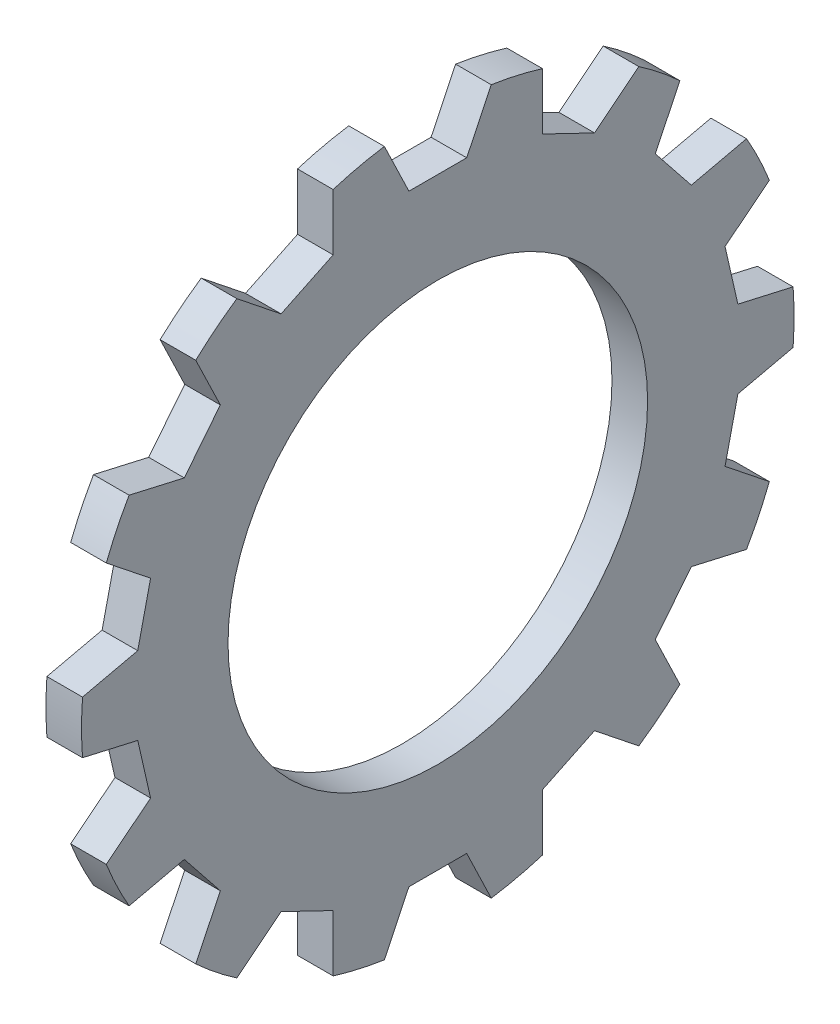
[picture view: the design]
ISO-10303-21;
HEADER;
FILE_DESCRIPTION(('STEP AP214'),'2;1');
FILE_NAME('part.step','',(''),(''),'','','');
FILE_SCHEMA(('AUTOMOTIVE_DESIGN { 1 0 10303 214 1 1 1 1 }'));
ENDSEC;
DATA;
#1=APPLICATION_CONTEXT('core data for automotive mechanical design processes');
#2=APPLICATION_PROTOCOL_DEFINITION('international standard','automotive_design',2000,#1);
#3=PRODUCT_CONTEXT('',#1,'mechanical');
#4=PRODUCT('Part','Part','',(#3));
#5=PRODUCT_RELATED_PRODUCT_CATEGORY('part','',(#4));
#6=PRODUCT_DEFINITION_FORMATION('','',#4);
#7=PRODUCT_DEFINITION_CONTEXT('part definition',#1,'design');
#8=PRODUCT_DEFINITION('design','',#6,#7);
#9=PRODUCT_DEFINITION_SHAPE('','',#8);
#10=(LENGTH_UNIT() NAMED_UNIT(*) SI_UNIT(.MILLI.,.METRE.));
#11=(NAMED_UNIT(*) PLANE_ANGLE_UNIT() SI_UNIT($,.RADIAN.));
#12=(NAMED_UNIT(*) SI_UNIT($,.STERADIAN.) SOLID_ANGLE_UNIT());
#13=UNCERTAINTY_MEASURE_WITH_UNIT(LENGTH_MEASURE(1.E-05),#10,'distance_accuracy_value','');
#14=(GEOMETRIC_REPRESENTATION_CONTEXT(3) GLOBAL_UNCERTAINTY_ASSIGNED_CONTEXT((#13)) GLOBAL_UNIT_ASSIGNED_CONTEXT((#10,
#11,#12)) REPRESENTATION_CONTEXT('',''));
#15=CARTESIAN_POINT('',(0.,0.,0.));
#16=DIRECTION('',(0.,0.,1.));
#17=DIRECTION('',(1.,0.,0.));
#18=AXIS2_PLACEMENT_3D('',#15,#16,#17);
#19=CARTESIAN_POINT('',(-1.143,0.,0.));
#20=DIRECTION('',(1.,0.,0.));
#21=DIRECTION('',(0.,0.,-1.));
#22=AXIS2_PLACEMENT_3D('',#19,#20,#21);
#23=CYLINDRICAL_SURFACE('',#22,11.43);
#24=DIRECTION('',(1.,0.,0.));
#25=VECTOR('',#24,1.);
#26=CARTESIAN_POINT('',(-1.143,8.38630939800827,7.76625486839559));
#27=LINE('',#26,#25);
#28=CARTESIAN_POINT('',(-1.143,8.38630939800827,7.76625486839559));
#29=VERTEX_POINT('',#28);
#30=CARTESIAN_POINT('',(0.,8.38630939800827,7.76625486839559));
#31=VERTEX_POINT('',#30);
#32=EDGE_CURVE('E476',#29,#31,#27,.T.);
#33=ORIENTED_EDGE('',*,*,#32,.T.);
#34=CARTESIAN_POINT('',(0.,0.,0.));
#35=DIRECTION('',(1.,0.,0.));
#36=DIRECTION('',(0.,0.,-1.));
#37=AXIS2_PLACEMENT_3D('',#34,#35,#36);
#38=CIRCLE('',#37,11.43);
#39=CARTESIAN_POINT('',(0.,9.43766804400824,6.44789282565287));
#40=VERTEX_POINT('',#39);
#41=EDGE_CURVE('E787',#40,#31,#38,.T.);
#42=ORIENTED_EDGE('',*,*,#41,.F.);
#43=DIRECTION('',(1.,0.,0.));
#44=VECTOR('',#43,1.);
#45=CARTESIAN_POINT('',(-1.143,9.43766804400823,6.44789282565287));
#46=LINE('',#45,#44);
#47=CARTESIAN_POINT('',(-1.143,9.43766804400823,6.44789282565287));
#48=VERTEX_POINT('',#47);
#49=EDGE_CURVE('E458',#48,#40,#46,.T.);
#50=ORIENTED_EDGE('',*,*,#49,.F.);
#51=CARTESIAN_POINT('',(-1.143,0.,0.));
#52=DIRECTION('',(1.,0.,0.));
#53=DIRECTION('',(0.,0.,-1.));
#54=AXIS2_PLACEMENT_3D('',#51,#52,#53);
#55=CIRCLE('',#54,11.43);
#56=EDGE_CURVE('E42',#48,#29,#55,.T.);
#57=ORIENTED_EDGE('',*,*,#56,.T.);
#58=EDGE_LOOP('',(#33,#42,#50,#57));
#59=FACE_BOUND('',#58,.T.);
#60=ADVANCED_FACE('F33',(#59),#23,.T.);
#61=DIRECTION('',(1.,0.,0.));
#62=VECTOR('',#61,1.);
#63=CARTESIAN_POINT('',(-1.143,5.70540924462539,9.90420139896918));
#64=LINE('',#63,#62);
#65=CARTESIAN_POINT('',(-1.143,5.70540924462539,9.90420139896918));
#66=VERTEX_POINT('',#65);
#67=CARTESIAN_POINT('',(0.,5.70540924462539,9.90420139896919));
#68=VERTEX_POINT('',#67);
#69=EDGE_CURVE('E393',#66,#68,#64,.T.);
#70=ORIENTED_EDGE('',*,*,#69,.F.);
#71=CARTESIAN_POINT('',(-1.143,4.18615198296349,10.6358371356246));
#72=VERTEX_POINT('',#71);
#73=EDGE_CURVE('E408',#66,#72,#55,.T.);
#74=ORIENTED_EDGE('',*,*,#73,.T.);
#75=DIRECTION('',(1.,0.,0.));
#76=VECTOR('',#75,1.);
#77=CARTESIAN_POINT('',(-1.143,4.18615198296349,10.6358371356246));
#78=LINE('',#77,#76);
#79=CARTESIAN_POINT('',(0.,4.18615198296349,10.6358371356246));
#80=VERTEX_POINT('',#79);
#81=EDGE_CURVE('E747',#72,#80,#78,.T.);
#82=ORIENTED_EDGE('',*,*,#81,.T.);
#83=EDGE_CURVE('E410',#68,#80,#38,.T.);
#84=ORIENTED_EDGE('',*,*,#83,.F.);
#85=EDGE_LOOP('',(#70,#74,#82,#84));
#86=FACE_BOUND('',#85,.T.);
#87=ADVANCED_FACE('F406',(#86),#23,.T.);
#88=DIRECTION('',(1.,0.,0.));
#89=VECTOR('',#88,1.);
#90=CARTESIAN_POINT('',(-1.143,0.843124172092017,11.3988614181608));
#91=LINE('',#90,#89);
#92=CARTESIAN_POINT('',(-1.143,0.843124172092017,11.3988614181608));
#93=VERTEX_POINT('',#92);
#94=CARTESIAN_POINT('',(0.,0.843124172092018,11.3988614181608));
#95=VERTEX_POINT('',#94);
#96=EDGE_CURVE('E741',#93,#95,#91,.T.);
#97=ORIENTED_EDGE('',*,*,#96,.F.);
#98=CARTESIAN_POINT('',(-1.143,-0.843124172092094,11.3988614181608));
#99=VERTEX_POINT('',#98);
#100=EDGE_CURVE('E418',#93,#99,#55,.T.);
#101=ORIENTED_EDGE('',*,*,#100,.T.);
#102=DIRECTION('',(1.,0.,0.));
#103=VECTOR('',#102,1.);
#104=CARTESIAN_POINT('',(-1.143,-0.843124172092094,11.3988614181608));
#105=LINE('',#104,#103);
#106=CARTESIAN_POINT('',(0.,-0.843124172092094,11.3988614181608));
#107=VERTEX_POINT('',#106);
#108=EDGE_CURVE('E722',#99,#107,#105,.T.);
#109=ORIENTED_EDGE('',*,*,#108,.T.);
#110=EDGE_CURVE('E794',#95,#107,#38,.T.);
#111=ORIENTED_EDGE('',*,*,#110,.F.);
#112=EDGE_LOOP('',(#97,#101,#109,#111));
#113=FACE_BOUND('',#112,.T.);
#114=ADVANCED_FACE('F989',(#113),#23,.T.);
#115=DIRECTION('',(1.,0.,0.));
#116=VECTOR('',#115,1.);
#117=CARTESIAN_POINT('',(-1.143,-4.18615198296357,10.6358371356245));
#118=LINE('',#117,#116);
#119=CARTESIAN_POINT('',(-1.143,-4.18615198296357,10.6358371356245));
#120=VERTEX_POINT('',#119);
#121=CARTESIAN_POINT('',(0.,-4.18615198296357,10.6358371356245));
#122=VERTEX_POINT('',#121);
#123=EDGE_CURVE('E715',#120,#122,#118,.T.);
#124=ORIENTED_EDGE('',*,*,#123,.F.);
#125=CARTESIAN_POINT('',(-1.143,-5.70540924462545,9.90420139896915));
#126=VERTEX_POINT('',#125);
#127=EDGE_CURVE('E421',#120,#126,#55,.T.);
#128=ORIENTED_EDGE('',*,*,#127,.T.);
#129=DIRECTION('',(1.,0.,0.));
#130=VECTOR('',#129,1.);
#131=CARTESIAN_POINT('',(-1.143,-5.70540924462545,9.90420139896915));
#132=LINE('',#131,#130);
#133=CARTESIAN_POINT('',(0.,-5.70540924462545,9.90420139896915));
#134=VERTEX_POINT('',#133);
#135=EDGE_CURVE('E696',#126,#134,#132,.T.);
#136=ORIENTED_EDGE('',*,*,#135,.T.);
#137=EDGE_CURVE('E797',#122,#134,#38,.T.);
#138=ORIENTED_EDGE('',*,*,#137,.F.);
#139=EDGE_LOOP('',(#124,#128,#136,#138));
#140=FACE_BOUND('',#139,.T.);
#141=ADVANCED_FACE('F897',(#140),#23,.T.);
#142=DIRECTION('',(1.,0.,0.));
#143=VECTOR('',#142,1.);
#144=CARTESIAN_POINT('',(-1.143,-8.38630939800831,7.76625486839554));
#145=LINE('',#144,#143);
#146=CARTESIAN_POINT('',(-1.143,-8.38630939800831,7.76625486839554));
#147=VERTEX_POINT('',#146);
#148=CARTESIAN_POINT('',(0.,-8.38630939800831,7.76625486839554));
#149=VERTEX_POINT('',#148);
#150=EDGE_CURVE('E689',#147,#149,#145,.T.);
#151=ORIENTED_EDGE('',*,*,#150,.F.);
#152=CARTESIAN_POINT('',(-1.143,-9.43766804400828,6.4478928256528));
#153=VERTEX_POINT('',#152);
#154=EDGE_CURVE('E885',#147,#153,#55,.T.);
#155=ORIENTED_EDGE('',*,*,#154,.T.);
#156=DIRECTION('',(1.,0.,0.));
#157=VECTOR('',#156,1.);
#158=CARTESIAN_POINT('',(-1.143,-9.43766804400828,6.4478928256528));
#159=LINE('',#158,#157);
#160=CARTESIAN_POINT('',(0.,-9.43766804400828,6.4478928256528));
#161=VERTEX_POINT('',#160);
#162=EDGE_CURVE('E670',#153,#161,#159,.T.);
#163=ORIENTED_EDGE('',*,*,#162,.T.);
#164=EDGE_CURVE('E802',#149,#161,#38,.T.);
#165=ORIENTED_EDGE('',*,*,#164,.F.);
#166=EDGE_LOOP('',(#151,#155,#163,#165));
#167=FACE_BOUND('',#166,.T.);
#168=ADVANCED_FACE('F907',(#167),#23,.T.);
#169=DIRECTION('',(1.,0.,0.));
#170=VECTOR('',#169,1.);
#171=CARTESIAN_POINT('',(-1.143,-10.9254553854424,3.3584705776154));
#172=LINE('',#171,#170);
#173=CARTESIAN_POINT('',(-1.143,-10.9254553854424,3.3584705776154));
#174=VERTEX_POINT('',#173);
#175=CARTESIAN_POINT('',(0.,-10.9254553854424,3.3584705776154));
#176=VERTEX_POINT('',#175);
#177=EDGE_CURVE('E663',#174,#176,#172,.T.);
#178=ORIENTED_EDGE('',*,*,#177,.F.);
#179=CARTESIAN_POINT('',(-1.143,-11.3006809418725,1.71449999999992));
#180=VERTEX_POINT('',#179);
#181=EDGE_CURVE('E880',#174,#180,#55,.T.);
#182=ORIENTED_EDGE('',*,*,#181,.T.);
#183=DIRECTION('',(1.,0.,0.));
#184=VECTOR('',#183,1.);
#185=CARTESIAN_POINT('',(-1.143,-11.3006809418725,1.71449999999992));
#186=LINE('',#185,#184);
#187=CARTESIAN_POINT('',(0.,-11.3006809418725,1.71449999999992));
#188=VERTEX_POINT('',#187);
#189=EDGE_CURVE('E644',#180,#188,#186,.T.);
#190=ORIENTED_EDGE('',*,*,#189,.T.);
#191=EDGE_CURVE('E807',#176,#188,#38,.T.);
#192=ORIENTED_EDGE('',*,*,#191,.F.);
#193=EDGE_LOOP('',(#178,#182,#190,#192));
#194=FACE_BOUND('',#193,.T.);
#195=ADVANCED_FACE('F917',(#194),#23,.T.);
#196=DIRECTION('',(1.,0.,0.));
#197=VECTOR('',#196,1.);
#198=CARTESIAN_POINT('',(-1.143,-11.3006809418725,-1.71450000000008));
#199=LINE('',#198,#197);
#200=CARTESIAN_POINT('',(-1.143,-11.3006809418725,-1.71450000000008));
#201=VERTEX_POINT('',#200);
#202=CARTESIAN_POINT('',(0.,-11.3006809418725,-1.71450000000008));
#203=VERTEX_POINT('',#202);
#204=EDGE_CURVE('E637',#201,#203,#199,.T.);
#205=ORIENTED_EDGE('',*,*,#204,.F.);
#206=CARTESIAN_POINT('',(-1.143,-10.9254553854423,-3.35847057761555));
#207=VERTEX_POINT('',#206);
#208=EDGE_CURVE('E875',#201,#207,#55,.T.);
#209=ORIENTED_EDGE('',*,*,#208,.T.);
#210=DIRECTION('',(1.,0.,0.));
#211=VECTOR('',#210,1.);
#212=CARTESIAN_POINT('',(-1.143,-10.9254553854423,-3.35847057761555));
#213=LINE('',#212,#211);
#214=CARTESIAN_POINT('',(0.,-10.9254553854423,-3.35847057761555));
#215=VERTEX_POINT('',#214);
#216=EDGE_CURVE('E618',#207,#215,#213,.T.);
#217=ORIENTED_EDGE('',*,*,#216,.T.);
#218=EDGE_CURVE('E812',#203,#215,#38,.T.);
#219=ORIENTED_EDGE('',*,*,#218,.F.);
#220=EDGE_LOOP('',(#205,#209,#217,#219));
#221=FACE_BOUND('',#220,.T.);
#222=ADVANCED_FACE('F927',(#221),#23,.T.);
#223=DIRECTION('',(1.,0.,0.));
#224=VECTOR('',#223,1.);
#225=CARTESIAN_POINT('',(-1.143,-9.43766804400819,-6.44789282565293));
#226=LINE('',#225,#224);
#227=CARTESIAN_POINT('',(-1.143,-9.43766804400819,-6.44789282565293));
#228=VERTEX_POINT('',#227);
#229=CARTESIAN_POINT('',(0.,-9.43766804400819,-6.44789282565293));
#230=VERTEX_POINT('',#229);
#231=EDGE_CURVE('E611',#228,#230,#226,.T.);
#232=ORIENTED_EDGE('',*,*,#231,.F.);
#233=CARTESIAN_POINT('',(-1.143,-8.38630939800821,-7.76625486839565));
#234=VERTEX_POINT('',#233);
#235=EDGE_CURVE('E870',#228,#234,#55,.T.);
#236=ORIENTED_EDGE('',*,*,#235,.T.);
#237=DIRECTION('',(1.,0.,0.));
#238=VECTOR('',#237,1.);
#239=CARTESIAN_POINT('',(-1.143,-8.38630939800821,-7.76625486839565));
#240=LINE('',#239,#238);
#241=CARTESIAN_POINT('',(0.,-8.38630939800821,-7.76625486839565));
#242=VERTEX_POINT('',#241);
#243=EDGE_CURVE('E592',#234,#242,#240,.T.);
#244=ORIENTED_EDGE('',*,*,#243,.T.);
#245=EDGE_CURVE('E817',#230,#242,#38,.T.);
#246=ORIENTED_EDGE('',*,*,#245,.F.);
#247=EDGE_LOOP('',(#232,#236,#244,#246));
#248=FACE_BOUND('',#247,.T.);
#249=ADVANCED_FACE('F937',(#248),#23,.T.);
#250=DIRECTION('',(1.,0.,0.));
#251=VECTOR('',#250,1.);
#252=CARTESIAN_POINT('',(-1.143,-5.70540924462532,-9.90420139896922));
#253=LINE('',#252,#251);
#254=CARTESIAN_POINT('',(-1.143,-5.70540924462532,-9.90420139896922));
#255=VERTEX_POINT('',#254);
#256=CARTESIAN_POINT('',(0.,-5.70540924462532,-9.90420139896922));
#257=VERTEX_POINT('',#256);
#258=EDGE_CURVE('E585',#255,#257,#253,.T.);
#259=ORIENTED_EDGE('',*,*,#258,.F.);
#260=CARTESIAN_POINT('',(-1.143,-4.18615198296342,-10.6358371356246));
#261=VERTEX_POINT('',#260);
#262=EDGE_CURVE('E865',#255,#261,#55,.T.);
#263=ORIENTED_EDGE('',*,*,#262,.T.);
#264=DIRECTION('',(1.,0.,0.));
#265=VECTOR('',#264,1.);
#266=CARTESIAN_POINT('',(-1.143,-4.18615198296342,-10.6358371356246));
#267=LINE('',#266,#265);
#268=CARTESIAN_POINT('',(0.,-4.18615198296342,-10.6358371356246));
#269=VERTEX_POINT('',#268);
#270=EDGE_CURVE('E566',#261,#269,#267,.T.);
#271=ORIENTED_EDGE('',*,*,#270,.T.);
#272=EDGE_CURVE('E822',#257,#269,#38,.T.);
#273=ORIENTED_EDGE('',*,*,#272,.F.);
#274=EDGE_LOOP('',(#259,#263,#271,#273));
#275=FACE_BOUND('',#274,.T.);
#276=ADVANCED_FACE('F947',(#275),#23,.T.);
#277=DIRECTION('',(1.,0.,0.));
#278=VECTOR('',#277,1.);
#279=CARTESIAN_POINT('',(-1.143,-0.843124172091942,-11.3988614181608));
#280=LINE('',#279,#278);
#281=CARTESIAN_POINT('',(-1.143,-0.843124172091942,-11.3988614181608));
#282=VERTEX_POINT('',#281);
#283=CARTESIAN_POINT('',(0.,-0.843124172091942,-11.3988614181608));
#284=VERTEX_POINT('',#283);
#285=EDGE_CURVE('E559',#282,#284,#280,.T.);
#286=ORIENTED_EDGE('',*,*,#285,.F.);
#287=CARTESIAN_POINT('',(-1.143,0.843124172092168,-11.3988614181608));
#288=VERTEX_POINT('',#287);
#289=EDGE_CURVE('E860',#282,#288,#55,.T.);
#290=ORIENTED_EDGE('',*,*,#289,.T.);
#291=DIRECTION('',(1.,0.,0.));
#292=VECTOR('',#291,1.);
#293=CARTESIAN_POINT('',(-1.143,0.843124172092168,-11.3988614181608));
#294=LINE('',#293,#292);
#295=CARTESIAN_POINT('',(0.,0.843124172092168,-11.3988614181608));
#296=VERTEX_POINT('',#295);
#297=EDGE_CURVE('E540',#288,#296,#294,.T.);
#298=ORIENTED_EDGE('',*,*,#297,.T.);
#299=EDGE_CURVE('E827',#284,#296,#38,.T.);
#300=ORIENTED_EDGE('',*,*,#299,.F.);
#301=EDGE_LOOP('',(#286,#290,#298,#300));
#302=FACE_BOUND('',#301,.T.);
#303=ADVANCED_FACE('F957',(#302),#23,.T.);
#304=DIRECTION('',(1.,0.,0.));
#305=VECTOR('',#304,1.);
#306=CARTESIAN_POINT('',(-1.143,4.18615198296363,-10.6358371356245));
#307=LINE('',#306,#305);
#308=CARTESIAN_POINT('',(-1.143,4.18615198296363,-10.6358371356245));
#309=VERTEX_POINT('',#308);
#310=CARTESIAN_POINT('',(0.,4.18615198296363,-10.6358371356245));
#311=VERTEX_POINT('',#310);
#312=EDGE_CURVE('E533',#309,#311,#307,.T.);
#313=ORIENTED_EDGE('',*,*,#312,.F.);
#314=CARTESIAN_POINT('',(-1.143,5.70540924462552,-9.9042013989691));
#315=VERTEX_POINT('',#314);
#316=EDGE_CURVE('E856',#309,#315,#55,.T.);
#317=ORIENTED_EDGE('',*,*,#316,.T.);
#318=DIRECTION('',(1.,0.,0.));
#319=VECTOR('',#318,1.);
#320=CARTESIAN_POINT('',(-1.143,5.70540924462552,-9.9042013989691));
#321=LINE('',#320,#319);
#322=CARTESIAN_POINT('',(0.,5.70540924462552,-9.9042013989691));
#323=VERTEX_POINT('',#322);
#324=EDGE_CURVE('E515',#315,#323,#321,.T.);
#325=ORIENTED_EDGE('',*,*,#324,.T.);
#326=EDGE_CURVE('E832',#311,#323,#38,.T.);
#327=ORIENTED_EDGE('',*,*,#326,.F.);
#328=EDGE_LOOP('',(#313,#317,#325,#327));
#329=FACE_BOUND('',#328,.T.);
#330=ADVANCED_FACE('F967',(#329),#23,.T.);
#331=DIRECTION('',(1.,0.,0.));
#332=VECTOR('',#331,1.);
#333=CARTESIAN_POINT('',(-1.143,8.38630939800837,-7.76625486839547));
#334=LINE('',#333,#332);
#335=CARTESIAN_POINT('',(-1.143,8.38630939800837,-7.76625486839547));
#336=VERTEX_POINT('',#335);
#337=CARTESIAN_POINT('',(0.,8.38630939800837,-7.76625486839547));
#338=VERTEX_POINT('',#337);
#339=EDGE_CURVE('E58',#336,#338,#334,.T.);
#340=ORIENTED_EDGE('',*,*,#339,.F.);
#341=CARTESIAN_POINT('',(-1.143,9.43766804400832,-6.44789282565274));
#342=VERTEX_POINT('',#341);
#343=EDGE_CURVE('E854',#336,#342,#55,.T.);
#344=ORIENTED_EDGE('',*,*,#343,.T.);
#345=DIRECTION('',(1.,0.,0.));
#346=VECTOR('',#345,1.);
#347=CARTESIAN_POINT('',(-1.143,9.43766804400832,-6.44789282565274));
#348=LINE('',#347,#346);
#349=CARTESIAN_POINT('',(0.,9.43766804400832,-6.44789282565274));
#350=VERTEX_POINT('',#349);
#351=EDGE_CURVE('E490',#342,#350,#348,.T.);
#352=ORIENTED_EDGE('',*,*,#351,.T.);
#353=EDGE_CURVE('E837',#338,#350,#38,.T.);
#354=ORIENTED_EDGE('',*,*,#353,.F.);
#355=EDGE_LOOP('',(#340,#344,#352,#354));
#356=FACE_BOUND('',#355,.T.);
#357=ADVANCED_FACE('F998',(#356),#23,.T.);
#358=DIRECTION('',(1.,0.,0.));
#359=VECTOR('',#358,1.);
#360=CARTESIAN_POINT('',(-1.143,10.9254553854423,3.35847057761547));
#361=LINE('',#360,#359);
#362=CARTESIAN_POINT('',(-1.143,10.9254553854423,3.35847057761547));
#363=VERTEX_POINT('',#362);
#364=CARTESIAN_POINT('',(0.,10.9254553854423,3.35847057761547));
#365=VERTEX_POINT('',#364);
#366=EDGE_CURVE('E450',#363,#365,#361,.T.);
#367=ORIENTED_EDGE('',*,*,#366,.T.);
#368=CARTESIAN_POINT('',(0.,11.3006809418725,1.7145));
#369=VERTEX_POINT('',#368);
#370=EDGE_CURVE('E37',#369,#365,#38,.T.);
#371=ORIENTED_EDGE('',*,*,#370,.F.);
#372=DIRECTION('',(1.,0.,0.));
#373=VECTOR('',#372,1.);
#374=CARTESIAN_POINT('',(-1.143,11.3006809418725,1.7145));
#375=LINE('',#374,#373);
#376=CARTESIAN_POINT('',(-1.143,11.3006809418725,1.7145));
#377=VERTEX_POINT('',#376);
#378=EDGE_CURVE('E431',#377,#369,#375,.T.);
#379=ORIENTED_EDGE('',*,*,#378,.F.);
#380=EDGE_CURVE('E11',#377,#363,#55,.T.);
#381=ORIENTED_EDGE('',*,*,#380,.T.);
#382=EDGE_LOOP('',(#367,#371,#379,#381));
#383=FACE_BOUND('',#382,.T.);
#384=ADVANCED_FACE('F991',(#383),#23,.T.);
#385=DIRECTION('',(1.,0.,0.));
#386=VECTOR('',#385,1.);
#387=CARTESIAN_POINT('',(-1.143,10.9254553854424,-3.35847057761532));
#388=LINE('',#387,#386);
#389=CARTESIAN_POINT('',(-1.143,10.9254553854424,-3.35847057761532));
#390=VERTEX_POINT('',#389);
#391=CARTESIAN_POINT('',(0.,10.9254553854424,-3.35847057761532));
#392=VERTEX_POINT('',#391);
#393=EDGE_CURVE('E50',#390,#392,#388,.T.);
#394=ORIENTED_EDGE('',*,*,#393,.F.);
#395=CARTESIAN_POINT('',(-1.143,11.3006809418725,-1.7145));
#396=VERTEX_POINT('',#395);
#397=EDGE_CURVE('E43',#390,#396,#55,.T.);
#398=ORIENTED_EDGE('',*,*,#397,.T.);
#399=DIRECTION('',(1.,0.,0.));
#400=VECTOR('',#399,1.);
#401=CARTESIAN_POINT('',(-1.143,11.3006809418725,-1.7145));
#402=LINE('',#401,#400);
#403=CARTESIAN_POINT('',(0.,11.3006809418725,-1.7145));
#404=VERTEX_POINT('',#403);
#405=EDGE_CURVE('E427',#396,#404,#402,.T.);
#406=ORIENTED_EDGE('',*,*,#405,.T.);
#407=EDGE_CURVE('E430',#392,#404,#38,.T.);
#408=ORIENTED_EDGE('',*,*,#407,.F.);
#409=EDGE_LOOP('',(#394,#398,#406,#408));
#410=FACE_BOUND('',#409,.T.);
#411=ADVANCED_FACE('F35',(#410),#23,.T.);
#412=CARTESIAN_POINT('',(-1.143,0.,0.));
#413=DIRECTION('',(1.,0.,0.));
#414=DIRECTION('',(0.,0.,-1.));
#415=AXIS2_PLACEMENT_3D('',#412,#413,#414);
#416=PLANE('',#415);
#417=CARTESIAN_POINT('',(-1.143,0.,0.));
#418=DIRECTION('',(1.,0.,0.));
#419=DIRECTION('',(0.,0.,-1.));
#420=AXIS2_PLACEMENT_3D('',#417,#418,#419);
#421=CIRCLE('',#420,6.731);
#422=CARTESIAN_POINT('',(-1.143,0.,-6.731));
#423=VERTEX_POINT('',#422);
#424=EDGE_CURVE('E426',#423,#423,#421,.T.);
#425=ORIENTED_EDGE('',*,*,#424,.T.);
#426=EDGE_LOOP('',(#425));
#427=FACE_BOUND('',#426,.T.);
#428=DIRECTION('',(0.,0.78183148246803,-0.623489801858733));
#429=VECTOR('',#428,1.);
#430=CARTESIAN_POINT('',(-1.143,5.30019496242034,8.13312410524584));
#431=LINE('',#430,#429);
#432=CARTESIAN_POINT('',(-1.143,5.30019496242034,8.13312410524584));
#433=VERTEX_POINT('',#432);
#434=CARTESIAN_POINT('',(-1.143,6.74980537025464,6.97709838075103));
#435=VERTEX_POINT('',#434);
#436=EDGE_CURVE('E400',#433,#435,#431,.T.);
#437=ORIENTED_EDGE('',*,*,#436,.T.);
#438=DIRECTION('',(0.,0.900741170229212,0.434356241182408));
#439=VECTOR('',#438,1.);
#440=CARTESIAN_POINT('',(-1.143,6.74980537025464,6.97709838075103));
#441=LINE('',#440,#439);
#442=EDGE_CURVE('E411',#435,#29,#441,.T.);
#443=ORIENTED_EDGE('',*,*,#442,.T.);
#444=ORIENTED_EDGE('',*,*,#56,.F.);
#445=DIRECTION('',(0.,-0.623899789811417,-0.781504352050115));
#446=VECTOR('',#445,1.);
#447=CARTESIAN_POINT('',(-1.143,8.30414095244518,5.02802320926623));
#448=LINE('',#447,#446);
#449=CARTESIAN_POINT('',(-1.143,8.30414095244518,5.02802320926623));
#450=VERTEX_POINT('',#449);
#451=EDGE_CURVE('E469',#48,#450,#448,.T.);
#452=ORIENTED_EDGE('',*,*,#451,.T.);
#453=DIRECTION('',(0.,0.433883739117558,-0.900968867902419));
#454=VECTOR('',#453,1.);
#455=CARTESIAN_POINT('',(-1.143,8.30414095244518,5.02802320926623));
#456=LINE('',#455,#454);
#457=CARTESIAN_POINT('',(-1.143,9.10861403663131,3.35751763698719));
#458=VERTEX_POINT('',#457);
#459=EDGE_CURVE('E479',#450,#458,#456,.T.);
#460=ORIENTED_EDGE('',*,*,#459,.T.);
#461=DIRECTION('',(0.,0.999999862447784,0.000524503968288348));
#462=VECTOR('',#461,1.);
#463=CARTESIAN_POINT('',(-1.143,9.10861403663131,3.35751763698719));
#464=LINE('',#463,#462);
#465=EDGE_CURVE('E461',#458,#363,#464,.T.);
#466=ORIENTED_EDGE('',*,*,#465,.T.);
#467=ORIENTED_EDGE('',*,*,#380,.F.);
#468=DIRECTION('',(0.,-0.901196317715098,-0.433411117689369));
#469=VECTOR('',#468,1.);
#470=CARTESIAN_POINT('',(-1.143,9.66334998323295,0.927060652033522));
#471=LINE('',#470,#469);
#472=CARTESIAN_POINT('',(-1.143,9.66334998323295,0.927060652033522));
#473=VERTEX_POINT('',#472);
#474=EDGE_CURVE('E443',#377,#473,#471,.T.);
#475=ORIENTED_EDGE('',*,*,#474,.T.);
#476=DIRECTION('',(0.,0.,-1.));
#477=VECTOR('',#476,1.);
#478=CARTESIAN_POINT('',(-1.143,9.66334998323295,0.927060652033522));
#479=LINE('',#478,#477);
#480=CARTESIAN_POINT('',(-1.143,9.66334998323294,-0.927060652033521));
#481=VERTEX_POINT('',#480);
#482=EDGE_CURVE('E453',#473,#481,#479,.T.);
#483=ORIENTED_EDGE('',*,*,#482,.T.);
#484=DIRECTION('',(0.,0.901196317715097,-0.43341111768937));
#485=VECTOR('',#484,1.);
#486=CARTESIAN_POINT('',(-1.143,9.66334998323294,-0.927060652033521));
#487=LINE('',#486,#485);
#488=EDGE_CURVE('E434',#481,#396,#487,.T.);
#489=ORIENTED_EDGE('',*,*,#488,.T.);
#490=ORIENTED_EDGE('',*,*,#397,.F.);
#491=DIRECTION('',(0.,-0.999999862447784,0.00052450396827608));
#492=VECTOR('',#491,1.);
#493=CARTESIAN_POINT('',(-1.143,9.10861403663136,-3.35751763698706));
#494=LINE('',#493,#492);
#495=CARTESIAN_POINT('',(-1.143,9.10861403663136,-3.35751763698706));
#496=VERTEX_POINT('',#495);
#497=EDGE_CURVE('E496',#390,#496,#494,.T.);
#498=ORIENTED_EDGE('',*,*,#497,.T.);
#499=DIRECTION('',(0.,-0.433883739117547,-0.900968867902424));
#500=VECTOR('',#499,1.);
#501=CARTESIAN_POINT('',(-1.143,9.10861403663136,-3.35751763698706));
#502=LINE('',#501,#500);
#503=CARTESIAN_POINT('',(-1.143,8.30414095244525,-5.02802320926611));
#504=VERTEX_POINT('',#503);
#505=EDGE_CURVE('E504',#496,#504,#502,.T.);
#506=ORIENTED_EDGE('',*,*,#505,.T.);
#507=DIRECTION('',(0.,0.623899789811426,-0.781504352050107));
#508=VECTOR('',#507,1.);
#509=CARTESIAN_POINT('',(-1.143,8.30414095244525,-5.02802320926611));
#510=LINE('',#509,#508);
#511=EDGE_CURVE('E486',#504,#342,#510,.T.);
#512=ORIENTED_EDGE('',*,*,#511,.T.);
#513=ORIENTED_EDGE('',*,*,#343,.F.);
#514=DIRECTION('',(0.,-0.900741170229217,0.434356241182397));
#515=VECTOR('',#514,1.);
#516=CARTESIAN_POINT('',(-1.143,6.74980537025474,-6.97709838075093));
#517=LINE('',#516,#515);
#518=CARTESIAN_POINT('',(-1.143,6.74980537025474,-6.97709838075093));
#519=VERTEX_POINT('',#518);
#520=EDGE_CURVE('E521',#336,#519,#517,.T.);
#521=ORIENTED_EDGE('',*,*,#520,.T.);
#522=DIRECTION('',(0.,-0.781831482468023,-0.623489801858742));
#523=VECTOR('',#522,1.);
#524=CARTESIAN_POINT('',(-1.143,6.74980537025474,-6.97709838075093));
#525=LINE('',#524,#523);
#526=CARTESIAN_POINT('',(-1.143,5.30019496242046,-8.13312410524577));
#527=VERTEX_POINT('',#526);
#528=EDGE_CURVE('E528',#519,#527,#525,.T.);
#529=ORIENTED_EDGE('',*,*,#528,.T.);
#530=DIRECTION('',(0.,0.223032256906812,-0.974811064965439));
#531=VECTOR('',#530,1.);
#532=CARTESIAN_POINT('',(-1.143,5.30019496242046,-8.13312410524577));
#533=LINE('',#532,#531);
#534=EDGE_CURVE('E511',#527,#315,#533,.T.);
#535=ORIENTED_EDGE('',*,*,#534,.T.);
#536=ORIENTED_EDGE('',*,*,#316,.F.);
#537=DIRECTION('',(0.,-0.62307964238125,0.782158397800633));
#538=VECTOR('',#537,1.);
#539=CARTESIAN_POINT('',(-1.143,3.05411496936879,-9.21477922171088));
#540=LINE('',#539,#538);
#541=CARTESIAN_POINT('',(-1.143,3.05411496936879,-9.21477922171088));
#542=VERTEX_POINT('',#541);
#543=EDGE_CURVE('E546',#309,#542,#540,.T.);
#544=ORIENTED_EDGE('',*,*,#543,.T.);
#545=DIRECTION('',(0.,-0.974927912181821,-0.222520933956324));
#546=VECTOR('',#545,1.);
#547=CARTESIAN_POINT('',(-1.143,3.05411496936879,-9.21477922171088));
#548=LINE('',#547,#546);
#549=CARTESIAN_POINT('',(-1.143,1.24648035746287,-9.62736002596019));
#550=VERTEX_POINT('',#549);
#551=EDGE_CURVE('E554',#542,#550,#548,.T.);
#552=ORIENTED_EDGE('',*,*,#551,.T.);
#553=DIRECTION('',(0.,-0.222009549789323,-0.975044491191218));
#554=VECTOR('',#553,1.);
#555=CARTESIAN_POINT('',(-1.143,1.24648035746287,-9.62736002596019));
#556=LINE('',#555,#554);
#557=EDGE_CURVE('E536',#550,#288,#556,.T.);
#558=ORIENTED_EDGE('',*,*,#557,.T.);
#559=ORIENTED_EDGE('',*,*,#289,.F.);
#560=DIRECTION('',(0.,-0.222009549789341,0.975044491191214));
#561=VECTOR('',#560,1.);
#562=CARTESIAN_POINT('',(-1.143,-1.24648035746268,-9.62736002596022));
#563=LINE('',#562,#561);
#564=CARTESIAN_POINT('',(-1.143,-1.24648035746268,-9.62736002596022));
#565=VERTEX_POINT('',#564);
#566=EDGE_CURVE('E572',#282,#565,#563,.T.);
#567=ORIENTED_EDGE('',*,*,#566,.T.);
#568=DIRECTION('',(0.,-0.974927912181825,0.222520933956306));
#569=VECTOR('',#568,1.);
#570=CARTESIAN_POINT('',(-1.143,-1.24648035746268,-9.62736002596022));
#571=LINE('',#570,#569);
#572=CARTESIAN_POINT('',(-1.143,-3.0541149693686,-9.21477922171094));
#573=VERTEX_POINT('',#572);
#574=EDGE_CURVE('E580',#565,#573,#571,.T.);
#575=ORIENTED_EDGE('',*,*,#574,.T.);
#576=DIRECTION('',(0.,-0.623079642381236,-0.782158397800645));
#577=VECTOR('',#576,1.);
#578=CARTESIAN_POINT('',(-1.143,-3.0541149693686,-9.21477922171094));
#579=LINE('',#578,#577);
#580=EDGE_CURVE('E562',#573,#261,#579,.T.);
#581=ORIENTED_EDGE('',*,*,#580,.T.);
#582=ORIENTED_EDGE('',*,*,#262,.F.);
#583=DIRECTION('',(0.,0.223032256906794,0.974811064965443));
#584=VECTOR('',#583,1.);
#585=CARTESIAN_POINT('',(-1.143,-5.30019496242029,-8.13312410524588));
#586=LINE('',#585,#584);
#587=CARTESIAN_POINT('',(-1.143,-5.30019496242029,-8.13312410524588));
#588=VERTEX_POINT('',#587);
#589=EDGE_CURVE('E598',#255,#588,#586,.T.);
#590=ORIENTED_EDGE('',*,*,#589,.T.);
#591=DIRECTION('',(0.,-0.781831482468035,0.623489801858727));
#592=VECTOR('',#591,1.);
#593=CARTESIAN_POINT('',(-1.143,-5.30019496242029,-8.13312410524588));
#594=LINE('',#593,#592);
#595=CARTESIAN_POINT('',(-1.143,-6.74980537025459,-6.97709838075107));
#596=VERTEX_POINT('',#595);
#597=EDGE_CURVE('E606',#588,#596,#594,.T.);
#598=ORIENTED_EDGE('',*,*,#597,.T.);
#599=DIRECTION('',(0.,-0.900741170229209,-0.434356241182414));
#600=VECTOR('',#599,1.);
#601=CARTESIAN_POINT('',(-1.143,-6.74980537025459,-6.97709838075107));
#602=LINE('',#601,#600);
#603=EDGE_CURVE('E588',#596,#234,#602,.T.);
#604=ORIENTED_EDGE('',*,*,#603,.T.);
#605=ORIENTED_EDGE('',*,*,#235,.F.);
#606=DIRECTION('',(0.,0.623899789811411,0.781504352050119));
#607=VECTOR('',#606,1.);
#608=CARTESIAN_POINT('',(-1.143,-8.30414095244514,-5.02802320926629));
#609=LINE('',#608,#607);
#610=CARTESIAN_POINT('',(-1.143,-8.30414095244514,-5.02802320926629));
#611=VERTEX_POINT('',#610);
#612=EDGE_CURVE('E624',#228,#611,#609,.T.);
#613=ORIENTED_EDGE('',*,*,#612,.T.);
#614=DIRECTION('',(0.,-0.433883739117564,0.900968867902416));
#615=VECTOR('',#614,1.);
#616=CARTESIAN_POINT('',(-1.143,-8.30414095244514,-5.02802320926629));
#617=LINE('',#616,#615);
#618=CARTESIAN_POINT('',(-1.143,-9.10861403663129,-3.35751763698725));
#619=VERTEX_POINT('',#618);
#620=EDGE_CURVE('E632',#611,#619,#617,.T.);
#621=ORIENTED_EDGE('',*,*,#620,.T.);
#622=DIRECTION('',(0.,-0.999999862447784,-0.000524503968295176));
#623=VECTOR('',#622,1.);
#624=CARTESIAN_POINT('',(-1.143,-9.10861403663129,-3.35751763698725));
#625=LINE('',#624,#623);
#626=EDGE_CURVE('E614',#619,#207,#625,.T.);
#627=ORIENTED_EDGE('',*,*,#626,.T.);
#628=ORIENTED_EDGE('',*,*,#208,.F.);
#629=DIRECTION('',(0.,0.901196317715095,0.433411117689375));
#630=VECTOR('',#629,1.);
#631=CARTESIAN_POINT('',(-1.143,-9.66334998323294,-0.92706065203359));
#632=LINE('',#631,#630);
#633=CARTESIAN_POINT('',(-1.143,-9.66334998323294,-0.92706065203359));
#634=VERTEX_POINT('',#633);
#635=EDGE_CURVE('E650',#201,#634,#632,.T.);
#636=ORIENTED_EDGE('',*,*,#635,.T.);
#637=DIRECTION('',(0.,0.,1.));
#638=VECTOR('',#637,1.);
#639=CARTESIAN_POINT('',(-1.143,-9.66334998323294,-0.92706065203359));
#640=LINE('',#639,#638);
#641=CARTESIAN_POINT('',(-1.143,-9.66334998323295,0.927060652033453));
#642=VERTEX_POINT('',#641);
#643=EDGE_CURVE('E658',#634,#642,#640,.T.);
#644=ORIENTED_EDGE('',*,*,#643,.T.);
#645=DIRECTION('',(0.,-0.9011963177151,0.433411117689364));
#646=VECTOR('',#645,1.);
#647=CARTESIAN_POINT('',(-1.143,-9.66334998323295,0.927060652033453));
#648=LINE('',#647,#646);
#649=EDGE_CURVE('E640',#642,#180,#648,.T.);
#650=ORIENTED_EDGE('',*,*,#649,.T.);
#651=ORIENTED_EDGE('',*,*,#181,.F.);
#652=DIRECTION('',(0.,0.999999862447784,-0.000524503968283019));
#653=VECTOR('',#652,1.);
#654=CARTESIAN_POINT('',(-1.143,-9.10861403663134,3.35751763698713));
#655=LINE('',#654,#653);
#656=CARTESIAN_POINT('',(-1.143,-9.10861403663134,3.35751763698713));
#657=VERTEX_POINT('',#656);
#658=EDGE_CURVE('E676',#174,#657,#655,.T.);
#659=ORIENTED_EDGE('',*,*,#658,.T.);
#660=DIRECTION('',(0.,0.433883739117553,0.900968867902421));
#661=VECTOR('',#660,1.);
#662=CARTESIAN_POINT('',(-1.143,-9.10861403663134,3.35751763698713));
#663=LINE('',#662,#661);
#664=CARTESIAN_POINT('',(-1.143,-8.30414095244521,5.02802320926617));
#665=VERTEX_POINT('',#664);
#666=EDGE_CURVE('E684',#657,#665,#663,.T.);
#667=ORIENTED_EDGE('',*,*,#666,.T.);
#668=DIRECTION('',(0.,-0.623899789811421,0.781504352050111));
#669=VECTOR('',#668,1.);
#670=CARTESIAN_POINT('',(-1.143,-8.30414095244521,5.02802320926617));
#671=LINE('',#670,#669);
#672=EDGE_CURVE('E666',#665,#153,#671,.T.);
#673=ORIENTED_EDGE('',*,*,#672,.T.);
#674=ORIENTED_EDGE('',*,*,#154,.F.);
#675=DIRECTION('',(0.,0.900741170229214,-0.434356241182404));
#676=VECTOR('',#675,1.);
#677=CARTESIAN_POINT('',(-1.143,-6.74980537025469,6.97709838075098));
#678=LINE('',#677,#676);
#679=CARTESIAN_POINT('',(-1.143,-6.74980537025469,6.97709838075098));
#680=VERTEX_POINT('',#679);
#681=EDGE_CURVE('E702',#147,#680,#678,.T.);
#682=ORIENTED_EDGE('',*,*,#681,.T.);
#683=DIRECTION('',(0.,0.781831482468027,0.623489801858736));
#684=VECTOR('',#683,1.);
#685=CARTESIAN_POINT('',(-1.143,-6.74980537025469,6.97709838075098));
#686=LINE('',#685,#684);
#687=CARTESIAN_POINT('',(-1.143,-5.3001949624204,8.13312410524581));
#688=VERTEX_POINT('',#687);
#689=EDGE_CURVE('E710',#680,#688,#686,.T.);
#690=ORIENTED_EDGE('',*,*,#689,.T.);
#691=DIRECTION('',(0.,-0.223032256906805,0.974811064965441));
#692=VECTOR('',#691,1.);
#693=CARTESIAN_POINT('',(-1.143,-5.3001949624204,8.13312410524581));
#694=LINE('',#693,#692);
#695=EDGE_CURVE('E692',#688,#126,#694,.T.);
#696=ORIENTED_EDGE('',*,*,#695,.T.);
#697=ORIENTED_EDGE('',*,*,#127,.F.);
#698=DIRECTION('',(0.,0.623079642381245,-0.782158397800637));
#699=VECTOR('',#698,1.);
#700=CARTESIAN_POINT('',(-1.143,-3.05411496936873,9.2147792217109));
#701=LINE('',#700,#699);
#702=CARTESIAN_POINT('',(-1.143,-3.05411496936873,9.2147792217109));
#703=VERTEX_POINT('',#702);
#704=EDGE_CURVE('E728',#120,#703,#701,.T.);
#705=ORIENTED_EDGE('',*,*,#704,.T.);
#706=DIRECTION('',(0.,0.974927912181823,0.222520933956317));
#707=VECTOR('',#706,1.);
#708=CARTESIAN_POINT('',(-1.143,-3.05411496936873,9.2147792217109));
#709=LINE('',#708,#707);
#710=CARTESIAN_POINT('',(-1.143,-1.24648035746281,9.6273600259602));
#711=VERTEX_POINT('',#710);
#712=EDGE_CURVE('E736',#703,#711,#709,.T.);
#713=ORIENTED_EDGE('',*,*,#712,.T.);
#714=DIRECTION('',(0.,0.22200954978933,0.975044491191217));
#715=VECTOR('',#714,1.);
#716=CARTESIAN_POINT('',(-1.143,-1.24648035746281,9.6273600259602));
#717=LINE('',#716,#715);
#718=EDGE_CURVE('E718',#711,#99,#717,.T.);
#719=ORIENTED_EDGE('',*,*,#718,.T.);
#720=ORIENTED_EDGE('',*,*,#100,.F.);
#721=DIRECTION('',(0.,0.222009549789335,-0.975044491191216));
#722=VECTOR('',#721,1.);
#723=CARTESIAN_POINT('',(-1.143,1.24648035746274,9.62736002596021));
#724=LINE('',#723,#722);
#725=CARTESIAN_POINT('',(-1.143,1.24648035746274,9.62736002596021));
#726=VERTEX_POINT('',#725);
#727=EDGE_CURVE('E752',#93,#726,#724,.T.);
#728=ORIENTED_EDGE('',*,*,#727,.T.);
#729=DIRECTION('',(0.,0.974927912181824,-0.222520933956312));
#730=VECTOR('',#729,1.);
#731=CARTESIAN_POINT('',(-1.143,1.24648035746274,9.62736002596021));
#732=LINE('',#731,#730);
#733=CARTESIAN_POINT('',(-1.143,3.05411496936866,9.21477922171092));
#734=VERTEX_POINT('',#733);
#735=EDGE_CURVE('E759',#726,#734,#732,.T.);
#736=ORIENTED_EDGE('',*,*,#735,.T.);
#737=DIRECTION('',(0.,0.623079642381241,0.78215839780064));
#738=VECTOR('',#737,1.);
#739=CARTESIAN_POINT('',(-1.143,3.05411496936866,9.21477922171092));
#740=LINE('',#739,#738);
#741=EDGE_CURVE('E417',#734,#72,#740,.T.);
#742=ORIENTED_EDGE('',*,*,#741,.T.);
#743=ORIENTED_EDGE('',*,*,#73,.F.);
#744=DIRECTION('',(0.,-0.2230322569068,-0.974811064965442));
#745=VECTOR('',#744,1.);
#746=CARTESIAN_POINT('',(-1.143,5.30019496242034,8.13312410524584));
#747=LINE('',#746,#745);
#748=EDGE_CURVE('E389',#66,#433,#747,.T.);
#749=ORIENTED_EDGE('',*,*,#748,.T.);
#750=EDGE_LOOP('',(#437,#443,#444,#452,#460,#466,#467,#475,#483,#489,#490,#498,#506,#512,#513,
#521,#529,#535,#536,#544,#552,#558,#559,#567,#575,#581,#582,#590,#598,#604,#605,#613,#621,#627,
#628,#636,#644,#650,#651,#659,#667,#673,#674,#682,#690,#696,#697,#705,#713,#719,#720,#728,#736,
#742,#743,#749));
#751=FACE_BOUND('',#750,.T.);
#752=ADVANCED_FACE('F414',(#427,#751),#416,.F.);
#753=CARTESIAN_POINT('',(0.,0.,0.));
#754=DIRECTION('',(1.,0.,0.));
#755=DIRECTION('',(0.,0.,-1.));
#756=AXIS2_PLACEMENT_3D('',#753,#754,#755);
#757=PLANE('',#756);
#758=DIRECTION('',(0.,0.900741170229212,0.434356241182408));
#759=VECTOR('',#758,1.);
#760=CARTESIAN_POINT('',(0.,6.74980537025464,6.97709838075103));
#761=LINE('',#760,#759);
#762=CARTESIAN_POINT('',(0.,6.74980537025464,6.97709838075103));
#763=VERTEX_POINT('',#762);
#764=EDGE_CURVE('E401',#763,#31,#761,.T.);
#765=ORIENTED_EDGE('',*,*,#764,.F.);
#766=DIRECTION('',(0.,0.78183148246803,-0.623489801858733));
#767=VECTOR('',#766,1.);
#768=CARTESIAN_POINT('',(0.,5.30019496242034,8.13312410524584));
#769=LINE('',#768,#767);
#770=CARTESIAN_POINT('',(0.,5.30019496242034,8.13312410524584));
#771=VERTEX_POINT('',#770);
#772=EDGE_CURVE('E769',#771,#763,#769,.T.);
#773=ORIENTED_EDGE('',*,*,#772,.F.);
#774=DIRECTION('',(0.,-0.2230322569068,-0.974811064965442));
#775=VECTOR('',#774,1.);
#776=CARTESIAN_POINT('',(0.,5.30019496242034,8.13312410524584));
#777=LINE('',#776,#775);
#778=EDGE_CURVE('E749',#68,#771,#777,.T.);
#779=ORIENTED_EDGE('',*,*,#778,.F.);
#780=ORIENTED_EDGE('',*,*,#83,.T.);
#781=DIRECTION('',(0.,0.623079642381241,0.78215839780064));
#782=VECTOR('',#781,1.);
#783=CARTESIAN_POINT('',(0.,3.05411496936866,9.21477922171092));
#784=LINE('',#783,#782);
#785=CARTESIAN_POINT('',(0.,3.05411496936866,9.21477922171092));
#786=VERTEX_POINT('',#785);
#787=EDGE_CURVE('E750',#786,#80,#784,.T.);
#788=ORIENTED_EDGE('',*,*,#787,.F.);
#789=DIRECTION('',(0.,0.974927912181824,-0.222520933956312));
#790=VECTOR('',#789,1.);
#791=CARTESIAN_POINT('',(0.,1.24648035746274,9.62736002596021));
#792=LINE('',#791,#790);
#793=CARTESIAN_POINT('',(0.,1.24648035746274,9.62736002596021));
#794=VERTEX_POINT('',#793);
#795=EDGE_CURVE('E753',#794,#786,#792,.T.);
#796=ORIENTED_EDGE('',*,*,#795,.F.);
#797=DIRECTION('',(0.,0.222009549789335,-0.975044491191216));
#798=VECTOR('',#797,1.);
#799=CARTESIAN_POINT('',(0.,1.24648035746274,9.62736002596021));
#800=LINE('',#799,#798);
#801=EDGE_CURVE('E725',#95,#794,#800,.T.);
#802=ORIENTED_EDGE('',*,*,#801,.F.);
#803=ORIENTED_EDGE('',*,*,#110,.T.);
#804=DIRECTION('',(0.,0.22200954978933,0.975044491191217));
#805=VECTOR('',#804,1.);
#806=CARTESIAN_POINT('',(0.,-1.24648035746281,9.6273600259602));
#807=LINE('',#806,#805);
#808=CARTESIAN_POINT('',(0.,-1.24648035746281,9.6273600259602));
#809=VERTEX_POINT('',#808);
#810=EDGE_CURVE('E726',#809,#107,#807,.T.);
#811=ORIENTED_EDGE('',*,*,#810,.F.);
#812=DIRECTION('',(0.,0.974927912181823,0.222520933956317));
#813=VECTOR('',#812,1.);
#814=CARTESIAN_POINT('',(0.,-3.05411496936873,9.2147792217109));
#815=LINE('',#814,#813);
#816=CARTESIAN_POINT('',(0.,-3.05411496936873,9.2147792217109));
#817=VERTEX_POINT('',#816);
#818=EDGE_CURVE('E729',#817,#809,#815,.T.);
#819=ORIENTED_EDGE('',*,*,#818,.F.);
#820=DIRECTION('',(0.,0.623079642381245,-0.782158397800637));
#821=VECTOR('',#820,1.);
#822=CARTESIAN_POINT('',(0.,-3.05411496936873,9.2147792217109));
#823=LINE('',#822,#821);
#824=EDGE_CURVE('E699',#122,#817,#823,.T.);
#825=ORIENTED_EDGE('',*,*,#824,.F.);
#826=ORIENTED_EDGE('',*,*,#137,.T.);
#827=DIRECTION('',(0.,-0.223032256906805,0.974811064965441));
#828=VECTOR('',#827,1.);
#829=CARTESIAN_POINT('',(0.,-5.3001949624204,8.13312410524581));
#830=LINE('',#829,#828);
#831=CARTESIAN_POINT('',(0.,-5.3001949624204,8.13312410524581));
#832=VERTEX_POINT('',#831);
#833=EDGE_CURVE('E700',#832,#134,#830,.T.);
#834=ORIENTED_EDGE('',*,*,#833,.F.);
#835=DIRECTION('',(0.,0.781831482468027,0.623489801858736));
#836=VECTOR('',#835,1.);
#837=CARTESIAN_POINT('',(0.,-6.74980537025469,6.97709838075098));
#838=LINE('',#837,#836);
#839=CARTESIAN_POINT('',(0.,-6.74980537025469,6.97709838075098));
#840=VERTEX_POINT('',#839);
#841=EDGE_CURVE('E703',#840,#832,#838,.T.);
#842=ORIENTED_EDGE('',*,*,#841,.F.);
#843=DIRECTION('',(0.,0.900741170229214,-0.434356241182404));
#844=VECTOR('',#843,1.);
#845=CARTESIAN_POINT('',(0.,-6.74980537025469,6.97709838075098));
#846=LINE('',#845,#844);
#847=EDGE_CURVE('E673',#149,#840,#846,.T.);
#848=ORIENTED_EDGE('',*,*,#847,.F.);
#849=ORIENTED_EDGE('',*,*,#164,.T.);
#850=DIRECTION('',(0.,-0.623899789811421,0.781504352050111));
#851=VECTOR('',#850,1.);
#852=CARTESIAN_POINT('',(0.,-8.30414095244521,5.02802320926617));
#853=LINE('',#852,#851);
#854=CARTESIAN_POINT('',(0.,-8.30414095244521,5.02802320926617));
#855=VERTEX_POINT('',#854);
#856=EDGE_CURVE('E674',#855,#161,#853,.T.);
#857=ORIENTED_EDGE('',*,*,#856,.F.);
#858=DIRECTION('',(0.,0.433883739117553,0.900968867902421));
#859=VECTOR('',#858,1.);
#860=CARTESIAN_POINT('',(0.,-9.10861403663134,3.35751763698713));
#861=LINE('',#860,#859);
#862=CARTESIAN_POINT('',(0.,-9.10861403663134,3.35751763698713));
#863=VERTEX_POINT('',#862);
#864=EDGE_CURVE('E677',#863,#855,#861,.T.);
#865=ORIENTED_EDGE('',*,*,#864,.F.);
#866=DIRECTION('',(0.,0.999999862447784,-0.000524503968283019));
#867=VECTOR('',#866,1.);
#868=CARTESIAN_POINT('',(0.,-9.10861403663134,3.35751763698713));
#869=LINE('',#868,#867);
#870=EDGE_CURVE('E647',#176,#863,#869,.T.);
#871=ORIENTED_EDGE('',*,*,#870,.F.);
#872=ORIENTED_EDGE('',*,*,#191,.T.);
#873=DIRECTION('',(0.,-0.9011963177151,0.433411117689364));
#874=VECTOR('',#873,1.);
#875=CARTESIAN_POINT('',(0.,-9.66334998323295,0.927060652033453));
#876=LINE('',#875,#874);
#877=CARTESIAN_POINT('',(0.,-9.66334998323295,0.927060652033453));
#878=VERTEX_POINT('',#877);
#879=EDGE_CURVE('E648',#878,#188,#876,.T.);
#880=ORIENTED_EDGE('',*,*,#879,.F.);
#881=DIRECTION('',(0.,0.,1.));
#882=VECTOR('',#881,1.);
#883=CARTESIAN_POINT('',(0.,-9.66334998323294,-0.92706065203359));
#884=LINE('',#883,#882);
#885=CARTESIAN_POINT('',(0.,-9.66334998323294,-0.92706065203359));
#886=VERTEX_POINT('',#885);
#887=EDGE_CURVE('E651',#886,#878,#884,.T.);
#888=ORIENTED_EDGE('',*,*,#887,.F.);
#889=DIRECTION('',(0.,0.901196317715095,0.433411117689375));
#890=VECTOR('',#889,1.);
#891=CARTESIAN_POINT('',(0.,-9.66334998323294,-0.92706065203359));
#892=LINE('',#891,#890);
#893=EDGE_CURVE('E621',#203,#886,#892,.T.);
#894=ORIENTED_EDGE('',*,*,#893,.F.);
#895=ORIENTED_EDGE('',*,*,#218,.T.);
#896=DIRECTION('',(0.,-0.999999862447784,-0.000524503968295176));
#897=VECTOR('',#896,1.);
#898=CARTESIAN_POINT('',(0.,-9.10861403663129,-3.35751763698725));
#899=LINE('',#898,#897);
#900=CARTESIAN_POINT('',(0.,-9.10861403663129,-3.35751763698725));
#901=VERTEX_POINT('',#900);
#902=EDGE_CURVE('E622',#901,#215,#899,.T.);
#903=ORIENTED_EDGE('',*,*,#902,.F.);
#904=DIRECTION('',(0.,-0.433883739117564,0.900968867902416));
#905=VECTOR('',#904,1.);
#906=CARTESIAN_POINT('',(0.,-8.30414095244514,-5.02802320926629));
#907=LINE('',#906,#905);
#908=CARTESIAN_POINT('',(0.,-8.30414095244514,-5.02802320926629));
#909=VERTEX_POINT('',#908);
#910=EDGE_CURVE('E625',#909,#901,#907,.T.);
#911=ORIENTED_EDGE('',*,*,#910,.F.);
#912=DIRECTION('',(0.,0.623899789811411,0.781504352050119));
#913=VECTOR('',#912,1.);
#914=CARTESIAN_POINT('',(0.,-8.30414095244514,-5.02802320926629));
#915=LINE('',#914,#913);
#916=EDGE_CURVE('E595',#230,#909,#915,.T.);
#917=ORIENTED_EDGE('',*,*,#916,.F.);
#918=ORIENTED_EDGE('',*,*,#245,.T.);
#919=DIRECTION('',(0.,-0.900741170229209,-0.434356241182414));
#920=VECTOR('',#919,1.);
#921=CARTESIAN_POINT('',(0.,-6.74980537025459,-6.97709838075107));
#922=LINE('',#921,#920);
#923=CARTESIAN_POINT('',(0.,-6.74980537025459,-6.97709838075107));
#924=VERTEX_POINT('',#923);
#925=EDGE_CURVE('E596',#924,#242,#922,.T.);
#926=ORIENTED_EDGE('',*,*,#925,.F.);
#927=DIRECTION('',(0.,-0.781831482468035,0.623489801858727));
#928=VECTOR('',#927,1.);
#929=CARTESIAN_POINT('',(0.,-5.30019496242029,-8.13312410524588));
#930=LINE('',#929,#928);
#931=CARTESIAN_POINT('',(0.,-5.30019496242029,-8.13312410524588));
#932=VERTEX_POINT('',#931);
#933=EDGE_CURVE('E599',#932,#924,#930,.T.);
#934=ORIENTED_EDGE('',*,*,#933,.F.);
#935=DIRECTION('',(0.,0.223032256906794,0.974811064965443));
#936=VECTOR('',#935,1.);
#937=CARTESIAN_POINT('',(0.,-5.30019496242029,-8.13312410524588));
#938=LINE('',#937,#936);
#939=EDGE_CURVE('E569',#257,#932,#938,.T.);
#940=ORIENTED_EDGE('',*,*,#939,.F.);
#941=ORIENTED_EDGE('',*,*,#272,.T.);
#942=DIRECTION('',(0.,-0.623079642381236,-0.782158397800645));
#943=VECTOR('',#942,1.);
#944=CARTESIAN_POINT('',(0.,-3.0541149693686,-9.21477922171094));
#945=LINE('',#944,#943);
#946=CARTESIAN_POINT('',(0.,-3.0541149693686,-9.21477922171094));
#947=VERTEX_POINT('',#946);
#948=EDGE_CURVE('E570',#947,#269,#945,.T.);
#949=ORIENTED_EDGE('',*,*,#948,.F.);
#950=DIRECTION('',(0.,-0.974927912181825,0.222520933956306));
#951=VECTOR('',#950,1.);
#952=CARTESIAN_POINT('',(0.,-1.24648035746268,-9.62736002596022));
#953=LINE('',#952,#951);
#954=CARTESIAN_POINT('',(0.,-1.24648035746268,-9.62736002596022));
#955=VERTEX_POINT('',#954);
#956=EDGE_CURVE('E573',#955,#947,#953,.T.);
#957=ORIENTED_EDGE('',*,*,#956,.F.);
#958=DIRECTION('',(0.,-0.222009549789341,0.975044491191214));
#959=VECTOR('',#958,1.);
#960=CARTESIAN_POINT('',(0.,-1.24648035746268,-9.62736002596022));
#961=LINE('',#960,#959);
#962=EDGE_CURVE('E543',#284,#955,#961,.T.);
#963=ORIENTED_EDGE('',*,*,#962,.F.);
#964=ORIENTED_EDGE('',*,*,#299,.T.);
#965=DIRECTION('',(0.,-0.222009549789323,-0.975044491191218));
#966=VECTOR('',#965,1.);
#967=CARTESIAN_POINT('',(0.,1.24648035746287,-9.62736002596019));
#968=LINE('',#967,#966);
#969=CARTESIAN_POINT('',(0.,1.24648035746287,-9.62736002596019));
#970=VERTEX_POINT('',#969);
#971=EDGE_CURVE('E544',#970,#296,#968,.T.);
#972=ORIENTED_EDGE('',*,*,#971,.F.);
#973=DIRECTION('',(0.,-0.974927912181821,-0.222520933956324));
#974=VECTOR('',#973,1.);
#975=CARTESIAN_POINT('',(0.,3.05411496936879,-9.21477922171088));
#976=LINE('',#975,#974);
#977=CARTESIAN_POINT('',(0.,3.05411496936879,-9.21477922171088));
#978=VERTEX_POINT('',#977);
#979=EDGE_CURVE('E547',#978,#970,#976,.T.);
#980=ORIENTED_EDGE('',*,*,#979,.F.);
#981=DIRECTION('',(0.,-0.62307964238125,0.782158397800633));
#982=VECTOR('',#981,1.);
#983=CARTESIAN_POINT('',(0.,3.05411496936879,-9.21477922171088));
#984=LINE('',#983,#982);
#985=EDGE_CURVE('E518',#311,#978,#984,.T.);
#986=ORIENTED_EDGE('',*,*,#985,.F.);
#987=ORIENTED_EDGE('',*,*,#326,.T.);
#988=DIRECTION('',(0.,0.223032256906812,-0.974811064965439));
#989=VECTOR('',#988,1.);
#990=CARTESIAN_POINT('',(0.,5.30019496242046,-8.13312410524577));
#991=LINE('',#990,#989);
#992=CARTESIAN_POINT('',(0.,5.30019496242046,-8.13312410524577));
#993=VERTEX_POINT('',#992);
#994=EDGE_CURVE('E519',#993,#323,#991,.T.);
#995=ORIENTED_EDGE('',*,*,#994,.F.);
#996=DIRECTION('',(0.,-0.781831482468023,-0.623489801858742));
#997=VECTOR('',#996,1.);
#998=CARTESIAN_POINT('',(0.,6.74980537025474,-6.97709838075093));
#999=LINE('',#998,#997);
#1000=CARTESIAN_POINT('',(0.,6.74980537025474,-6.97709838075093));
#1001=VERTEX_POINT('',#1000);
#1002=EDGE_CURVE('E522',#1001,#993,#999,.T.);
#1003=ORIENTED_EDGE('',*,*,#1002,.F.);
#1004=DIRECTION('',(0.,-0.900741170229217,0.434356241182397));
#1005=VECTOR('',#1004,1.);
#1006=CARTESIAN_POINT('',(0.,6.74980537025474,-6.97709838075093));
#1007=LINE('',#1006,#1005);
#1008=EDGE_CURVE('E493',#338,#1001,#1007,.T.);
#1009=ORIENTED_EDGE('',*,*,#1008,.F.);
#1010=ORIENTED_EDGE('',*,*,#353,.T.);
#1011=DIRECTION('',(0.,0.623899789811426,-0.781504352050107));
#1012=VECTOR('',#1011,1.);
#1013=CARTESIAN_POINT('',(0.,8.30414095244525,-5.02802320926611));
#1014=LINE('',#1013,#1012);
#1015=CARTESIAN_POINT('',(0.,8.30414095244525,-5.02802320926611));
#1016=VERTEX_POINT('',#1015);
#1017=EDGE_CURVE('E494',#1016,#350,#1014,.T.);
#1018=ORIENTED_EDGE('',*,*,#1017,.F.);
#1019=DIRECTION('',(0.,-0.433883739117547,-0.900968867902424));
#1020=VECTOR('',#1019,1.);
#1021=CARTESIAN_POINT('',(0.,9.10861403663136,-3.35751763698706));
#1022=LINE('',#1021,#1020);
#1023=CARTESIAN_POINT('',(0.,9.10861403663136,-3.35751763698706));
#1024=VERTEX_POINT('',#1023);
#1025=EDGE_CURVE('E497',#1024,#1016,#1022,.T.);
#1026=ORIENTED_EDGE('',*,*,#1025,.F.);
#1027=DIRECTION('',(0.,-0.999999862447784,0.00052450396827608));
#1028=VECTOR('',#1027,1.);
#1029=CARTESIAN_POINT('',(0.,9.10861403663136,-3.35751763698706));
#1030=LINE('',#1029,#1028);
#1031=EDGE_CURVE('E500',#392,#1024,#1030,.T.);
#1032=ORIENTED_EDGE('',*,*,#1031,.F.);
#1033=ORIENTED_EDGE('',*,*,#407,.T.);
#1034=DIRECTION('',(0.,0.901196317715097,-0.43341111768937));
#1035=VECTOR('',#1034,1.);
#1036=CARTESIAN_POINT('',(0.,9.66334998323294,-0.927060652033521));
#1037=LINE('',#1036,#1035);
#1038=CARTESIAN_POINT('',(0.,9.66334998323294,-0.927060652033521));
#1039=VERTEX_POINT('',#1038);
#1040=EDGE_CURVE('E440',#1039,#404,#1037,.T.);
#1041=ORIENTED_EDGE('',*,*,#1040,.F.);
#1042=DIRECTION('',(0.,0.,-1.));
#1043=VECTOR('',#1042,1.);
#1044=CARTESIAN_POINT('',(0.,9.66334998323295,0.927060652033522));
#1045=LINE('',#1044,#1043);
#1046=CARTESIAN_POINT('',(0.,9.66334998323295,0.927060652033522));
#1047=VERTEX_POINT('',#1046);
#1048=EDGE_CURVE('E444',#1047,#1039,#1045,.T.);
#1049=ORIENTED_EDGE('',*,*,#1048,.F.);
#1050=DIRECTION('',(0.,-0.901196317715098,-0.433411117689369));
#1051=VECTOR('',#1050,1.);
#1052=CARTESIAN_POINT('',(0.,9.66334998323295,0.927060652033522));
#1053=LINE('',#1052,#1051);
#1054=EDGE_CURVE('E447',#369,#1047,#1053,.T.);
#1055=ORIENTED_EDGE('',*,*,#1054,.F.);
#1056=ORIENTED_EDGE('',*,*,#370,.T.);
#1057=DIRECTION('',(0.,0.999999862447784,0.000524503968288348));
#1058=VECTOR('',#1057,1.);
#1059=CARTESIAN_POINT('',(0.,9.10861403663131,3.35751763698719));
#1060=LINE('',#1059,#1058);
#1061=CARTESIAN_POINT('',(0.,9.10861403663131,3.35751763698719));
#1062=VERTEX_POINT('',#1061);
#1063=EDGE_CURVE('E467',#1062,#365,#1060,.T.);
#1064=ORIENTED_EDGE('',*,*,#1063,.F.);
#1065=DIRECTION('',(0.,0.433883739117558,-0.900968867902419));
#1066=VECTOR('',#1065,1.);
#1067=CARTESIAN_POINT('',(0.,8.30414095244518,5.02802320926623));
#1068=LINE('',#1067,#1066);
#1069=CARTESIAN_POINT('',(0.,8.30414095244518,5.02802320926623));
#1070=VERTEX_POINT('',#1069);
#1071=EDGE_CURVE('E470',#1070,#1062,#1068,.T.);
#1072=ORIENTED_EDGE('',*,*,#1071,.F.);
#1073=DIRECTION('',(0.,-0.623899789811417,-0.781504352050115));
#1074=VECTOR('',#1073,1.);
#1075=CARTESIAN_POINT('',(0.,8.30414095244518,5.02802320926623));
#1076=LINE('',#1075,#1074);
#1077=EDGE_CURVE('E473',#40,#1070,#1076,.T.);
#1078=ORIENTED_EDGE('',*,*,#1077,.F.);
#1079=ORIENTED_EDGE('',*,*,#41,.T.);
#1080=EDGE_LOOP('',(#765,#773,#779,#780,#788,#796,#802,#803,#811,#819,#825,#826,#834,#842,#848,
#849,#857,#865,#871,#872,#880,#888,#894,#895,#903,#911,#917,#918,#926,#934,#940,#941,#949,#957,
#963,#964,#972,#980,#986,#987,#995,#1003,#1009,#1010,#1018,#1026,#1032,#1033,#1041,#1049,#1055,
#1056,#1064,#1072,#1078,#1079));
#1081=FACE_BOUND('',#1080,.T.);
#1082=CARTESIAN_POINT('',(0.,0.,0.));
#1083=DIRECTION('',(1.,0.,0.));
#1084=DIRECTION('',(0.,0.,-1.));
#1085=AXIS2_PLACEMENT_3D('',#1082,#1083,#1084);
#1086=CIRCLE('',#1085,6.731);
#1087=CARTESIAN_POINT('',(0.,0.,-6.731));
#1088=VERTEX_POINT('',#1087);
#1089=EDGE_CURVE('E423',#1088,#1088,#1086,.T.);
#1090=ORIENTED_EDGE('',*,*,#1089,.F.);
#1091=EDGE_LOOP('',(#1090));
#1092=FACE_BOUND('',#1091,.T.);
#1093=ADVANCED_FACE('F790',(#1081,#1092),#757,.T.);
#1094=CARTESIAN_POINT('',(-1.143,0.,0.));
#1095=DIRECTION('',(1.,0.,0.));
#1096=DIRECTION('',(0.,0.,-1.));
#1097=AXIS2_PLACEMENT_3D('',#1094,#1095,#1096);
#1098=CYLINDRICAL_SURFACE('',#1097,6.731);
#1099=ORIENTED_EDGE('',*,*,#424,.F.);
#1100=EDGE_LOOP('',(#1099));
#1101=FACE_BOUND('',#1100,.T.);
#1102=ORIENTED_EDGE('',*,*,#1089,.T.);
#1103=EDGE_LOOP('',(#1102));
#1104=FACE_BOUND('',#1103,.T.);
#1105=ADVANCED_FACE('F1034',(#1101,#1104),#1098,.F.);
#1106=CARTESIAN_POINT('',(-1.143,9.66334998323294,-0.927060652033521));
#1107=DIRECTION('',(0.,-0.43341111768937,-0.901196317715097));
#1108=DIRECTION('',(0.,0.901196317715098,-0.43341111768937));
#1109=AXIS2_PLACEMENT_3D('',#1106,#1107,#1108);
#1110=PLANE('',#1109);
#1111=ORIENTED_EDGE('',*,*,#1040,.T.);
#1112=ORIENTED_EDGE('',*,*,#405,.F.);
#1113=ORIENTED_EDGE('',*,*,#488,.F.);
#1114=DIRECTION('',(1.,0.,0.));
#1115=VECTOR('',#1114,1.);
#1116=CARTESIAN_POINT('',(-1.143,9.66334998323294,-0.927060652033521));
#1117=LINE('',#1116,#1115);
#1118=EDGE_CURVE('E436',#481,#1039,#1117,.T.);
#1119=ORIENTED_EDGE('',*,*,#1118,.T.);
#1120=EDGE_LOOP('',(#1111,#1112,#1113,#1119));
#1121=FACE_BOUND('',#1120,.T.);
#1122=ADVANCED_FACE('F851',(#1121),#1110,.F.);
#1123=CARTESIAN_POINT('',(-1.143,9.66334998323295,0.927060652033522));
#1124=DIRECTION('',(0.,-1.,0.));
#1125=DIRECTION('',(0.,0.,-1.));
#1126=AXIS2_PLACEMENT_3D('',#1123,#1124,#1125);
#1127=PLANE('',#1126);
#1128=ORIENTED_EDGE('',*,*,#1048,.T.);
#1129=ORIENTED_EDGE('',*,*,#1118,.F.);
#1130=ORIENTED_EDGE('',*,*,#482,.F.);
#1131=DIRECTION('',(1.,0.,0.));
#1132=VECTOR('',#1131,1.);
#1133=CARTESIAN_POINT('',(-1.143,9.66334998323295,0.927060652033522));
#1134=LINE('',#1133,#1132);
#1135=EDGE_CURVE('E433',#473,#1047,#1134,.T.);
#1136=ORIENTED_EDGE('',*,*,#1135,.T.);
#1137=EDGE_LOOP('',(#1128,#1129,#1130,#1136));
#1138=FACE_BOUND('',#1137,.T.);
#1139=ADVANCED_FACE('F1033',(#1138),#1127,.F.);
#1140=CARTESIAN_POINT('',(-1.143,9.66334998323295,0.927060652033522));
#1141=DIRECTION('',(0.,-0.433411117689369,0.901196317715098));
#1142=DIRECTION('',(0.,-0.901196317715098,-0.433411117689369));
#1143=AXIS2_PLACEMENT_3D('',#1140,#1141,#1142);
#1144=PLANE('',#1143);
#1145=ORIENTED_EDGE('',*,*,#1054,.T.);
#1146=ORIENTED_EDGE('',*,*,#1135,.F.);
#1147=ORIENTED_EDGE('',*,*,#474,.F.);
#1148=ORIENTED_EDGE('',*,*,#378,.T.);
#1149=EDGE_LOOP('',(#1145,#1146,#1147,#1148));
#1150=FACE_BOUND('',#1149,.T.);
#1151=ADVANCED_FACE('F1011',(#1150),#1144,.F.);
#1152=CARTESIAN_POINT('',(-1.143,9.10861403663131,3.35751763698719));
#1153=DIRECTION('',(0.,0.000524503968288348,-0.999999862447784));
#1154=DIRECTION('',(0.,0.999999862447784,0.000524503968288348));
#1155=AXIS2_PLACEMENT_3D('',#1152,#1153,#1154);
#1156=PLANE('',#1155);
#1157=ORIENTED_EDGE('',*,*,#1063,.T.);
#1158=ORIENTED_EDGE('',*,*,#366,.F.);
#1159=ORIENTED_EDGE('',*,*,#465,.F.);
#1160=DIRECTION('',(1.,0.,0.));
#1161=VECTOR('',#1160,1.);
#1162=CARTESIAN_POINT('',(-1.143,9.10861403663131,3.35751763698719));
#1163=LINE('',#1162,#1161);
#1164=EDGE_CURVE('E463',#458,#1062,#1163,.T.);
#1165=ORIENTED_EDGE('',*,*,#1164,.T.);
#1166=EDGE_LOOP('',(#1157,#1158,#1159,#1165));
#1167=FACE_BOUND('',#1166,.T.);
#1168=ADVANCED_FACE('F1014',(#1167),#1156,.F.);
#1169=CARTESIAN_POINT('',(-1.143,8.30414095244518,5.02802320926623));
#1170=DIRECTION('',(0.,-0.900968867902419,-0.433883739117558));
#1171=DIRECTION('',(0.,0.433883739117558,-0.900968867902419));
#1172=AXIS2_PLACEMENT_3D('',#1169,#1170,#1171);
#1173=PLANE('',#1172);
#1174=ORIENTED_EDGE('',*,*,#1071,.T.);
#1175=ORIENTED_EDGE('',*,*,#1164,.F.);
#1176=ORIENTED_EDGE('',*,*,#459,.F.);
#1177=DIRECTION('',(1.,0.,0.));
#1178=VECTOR('',#1177,1.);
#1179=CARTESIAN_POINT('',(-1.143,8.30414095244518,5.02802320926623));
#1180=LINE('',#1179,#1178);
#1181=EDGE_CURVE('E460',#450,#1070,#1180,.T.);
#1182=ORIENTED_EDGE('',*,*,#1181,.T.);
#1183=EDGE_LOOP('',(#1174,#1175,#1176,#1182));
#1184=FACE_BOUND('',#1183,.T.);
#1185=ADVANCED_FACE('F1016',(#1184),#1173,.F.);
#1186=CARTESIAN_POINT('',(-1.143,8.30414095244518,5.02802320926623));
#1187=DIRECTION('',(0.,-0.781504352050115,0.623899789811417));
#1188=DIRECTION('',(0.,-0.623899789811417,-0.781504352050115));
#1189=AXIS2_PLACEMENT_3D('',#1186,#1187,#1188);
#1190=PLANE('',#1189);
#1191=ORIENTED_EDGE('',*,*,#1077,.T.);
#1192=ORIENTED_EDGE('',*,*,#1181,.F.);
#1193=ORIENTED_EDGE('',*,*,#451,.F.);
#1194=ORIENTED_EDGE('',*,*,#49,.T.);
#1195=EDGE_LOOP('',(#1191,#1192,#1193,#1194));
#1196=FACE_BOUND('',#1195,.T.);
#1197=ADVANCED_FACE('F1018',(#1196),#1190,.F.);
#1198=CARTESIAN_POINT('',(-1.143,8.30414095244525,-5.02802320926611));
#1199=DIRECTION('',(0.,-0.781504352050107,-0.623899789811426));
#1200=DIRECTION('',(0.,0.623899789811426,-0.781504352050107));
#1201=AXIS2_PLACEMENT_3D('',#1198,#1199,#1200);
#1202=PLANE('',#1201);
#1203=ORIENTED_EDGE('',*,*,#1017,.T.);
#1204=ORIENTED_EDGE('',*,*,#351,.F.);
#1205=ORIENTED_EDGE('',*,*,#511,.F.);
#1206=DIRECTION('',(1.,0.,0.));
#1207=VECTOR('',#1206,1.);
#1208=CARTESIAN_POINT('',(-1.143,8.30414095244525,-5.02802320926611));
#1209=LINE('',#1208,#1207);
#1210=EDGE_CURVE('E488',#504,#1016,#1209,.T.);
#1211=ORIENTED_EDGE('',*,*,#1210,.T.);
#1212=EDGE_LOOP('',(#1203,#1204,#1205,#1211));
#1213=FACE_BOUND('',#1212,.T.);
#1214=ADVANCED_FACE('F1020',(#1213),#1202,.F.);
#1215=CARTESIAN_POINT('',(-1.143,9.10861403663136,-3.35751763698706));
#1216=DIRECTION('',(0.,-0.900968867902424,0.433883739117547));
#1217=DIRECTION('',(0.,-0.433883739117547,-0.900968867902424));
#1218=AXIS2_PLACEMENT_3D('',#1215,#1216,#1217);
#1219=PLANE('',#1218);
#1220=ORIENTED_EDGE('',*,*,#1025,.T.);
#1221=ORIENTED_EDGE('',*,*,#1210,.F.);
#1222=ORIENTED_EDGE('',*,*,#505,.F.);
#1223=DIRECTION('',(1.,0.,0.));
#1224=VECTOR('',#1223,1.);
#1225=CARTESIAN_POINT('',(-1.143,9.10861403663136,-3.35751763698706));
#1226=LINE('',#1225,#1224);
#1227=EDGE_CURVE('E485',#496,#1024,#1226,.T.);
#1228=ORIENTED_EDGE('',*,*,#1227,.T.);
#1229=EDGE_LOOP('',(#1220,#1221,#1222,#1228));
#1230=FACE_BOUND('',#1229,.T.);
#1231=ADVANCED_FACE('F1026',(#1230),#1219,.F.);
#1232=CARTESIAN_POINT('',(-1.143,9.10861403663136,-3.35751763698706));
#1233=DIRECTION('',(0.,0.00052450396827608,0.999999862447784));
#1234=DIRECTION('',(0.,-0.999999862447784,0.00052450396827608));
#1235=AXIS2_PLACEMENT_3D('',#1232,#1233,#1234);
#1236=PLANE('',#1235);
#1237=ORIENTED_EDGE('',*,*,#1031,.T.);
#1238=ORIENTED_EDGE('',*,*,#1227,.F.);
#1239=ORIENTED_EDGE('',*,*,#497,.F.);
#1240=ORIENTED_EDGE('',*,*,#393,.T.);
#1241=EDGE_LOOP('',(#1237,#1238,#1239,#1240));
#1242=FACE_BOUND('',#1241,.T.);
#1243=ADVANCED_FACE('F1091',(#1242),#1236,.F.);
#1244=CARTESIAN_POINT('',(-1.143,5.30019496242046,-8.13312410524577));
#1245=DIRECTION('',(0.,-0.974811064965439,-0.223032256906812));
#1246=DIRECTION('',(0.,0.223032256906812,-0.974811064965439));
#1247=AXIS2_PLACEMENT_3D('',#1244,#1245,#1246);
#1248=PLANE('',#1247);
#1249=ORIENTED_EDGE('',*,*,#994,.T.);
#1250=ORIENTED_EDGE('',*,*,#324,.F.);
#1251=ORIENTED_EDGE('',*,*,#534,.F.);
#1252=DIRECTION('',(1.,0.,0.));
#1253=VECTOR('',#1252,1.);
#1254=CARTESIAN_POINT('',(-1.143,5.30019496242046,-8.13312410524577));
#1255=LINE('',#1254,#1253);
#1256=EDGE_CURVE('E513',#527,#993,#1255,.T.);
#1257=ORIENTED_EDGE('',*,*,#1256,.T.);
#1258=EDGE_LOOP('',(#1249,#1250,#1251,#1257));
#1259=FACE_BOUND('',#1258,.T.);
#1260=ADVANCED_FACE('F971',(#1259),#1248,.F.);
#1261=CARTESIAN_POINT('',(-1.143,6.74980537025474,-6.97709838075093));
#1262=DIRECTION('',(0.,-0.623489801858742,0.781831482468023));
#1263=DIRECTION('',(0.,-0.781831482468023,-0.623489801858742));
#1264=AXIS2_PLACEMENT_3D('',#1261,#1262,#1263);
#1265=PLANE('',#1264);
#1266=ORIENTED_EDGE('',*,*,#1002,.T.);
#1267=ORIENTED_EDGE('',*,*,#1256,.F.);
#1268=ORIENTED_EDGE('',*,*,#528,.F.);
#1269=DIRECTION('',(1.,0.,0.));
#1270=VECTOR('',#1269,1.);
#1271=CARTESIAN_POINT('',(-1.143,6.74980537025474,-6.97709838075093));
#1272=LINE('',#1271,#1270);
#1273=EDGE_CURVE('E510',#519,#1001,#1272,.T.);
#1274=ORIENTED_EDGE('',*,*,#1273,.T.);
#1275=EDGE_LOOP('',(#1266,#1267,#1268,#1274));
#1276=FACE_BOUND('',#1275,.T.);
#1277=ADVANCED_FACE('F974',(#1276),#1265,.F.);
#1278=CARTESIAN_POINT('',(-1.143,6.74980537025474,-6.97709838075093));
#1279=DIRECTION('',(0.,0.434356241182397,0.900741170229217));
#1280=DIRECTION('',(0.,-0.900741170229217,0.434356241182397));
#1281=AXIS2_PLACEMENT_3D('',#1278,#1279,#1280);
#1282=PLANE('',#1281);
#1283=ORIENTED_EDGE('',*,*,#1008,.T.);
#1284=ORIENTED_EDGE('',*,*,#1273,.F.);
#1285=ORIENTED_EDGE('',*,*,#520,.F.);
#1286=ORIENTED_EDGE('',*,*,#339,.T.);
#1287=EDGE_LOOP('',(#1283,#1284,#1285,#1286));
#1288=FACE_BOUND('',#1287,.T.);
#1289=ADVANCED_FACE('F975',(#1288),#1282,.F.);
#1290=CARTESIAN_POINT('',(-1.143,1.24648035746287,-9.62736002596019));
#1291=DIRECTION('',(0.,-0.975044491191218,0.222009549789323));
#1292=DIRECTION('',(0.,-0.222009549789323,-0.975044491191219));
#1293=AXIS2_PLACEMENT_3D('',#1290,#1291,#1292);
#1294=PLANE('',#1293);
#1295=ORIENTED_EDGE('',*,*,#971,.T.);
#1296=ORIENTED_EDGE('',*,*,#297,.F.);
#1297=ORIENTED_EDGE('',*,*,#557,.F.);
#1298=DIRECTION('',(1.,0.,0.));
#1299=VECTOR('',#1298,1.);
#1300=CARTESIAN_POINT('',(-1.143,1.24648035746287,-9.62736002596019));
#1301=LINE('',#1300,#1299);
#1302=EDGE_CURVE('E538',#550,#970,#1301,.T.);
#1303=ORIENTED_EDGE('',*,*,#1302,.T.);
#1304=EDGE_LOOP('',(#1295,#1296,#1297,#1303));
#1305=FACE_BOUND('',#1304,.T.);
#1306=ADVANCED_FACE('F961',(#1305),#1294,.F.);
#1307=CARTESIAN_POINT('',(-1.143,3.05411496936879,-9.21477922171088));
#1308=DIRECTION('',(0.,-0.222520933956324,0.974927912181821));
#1309=DIRECTION('',(0.,-0.974927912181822,-0.222520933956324));
#1310=AXIS2_PLACEMENT_3D('',#1307,#1308,#1309);
#1311=PLANE('',#1310);
#1312=ORIENTED_EDGE('',*,*,#979,.T.);
#1313=ORIENTED_EDGE('',*,*,#1302,.F.);
#1314=ORIENTED_EDGE('',*,*,#551,.F.);
#1315=DIRECTION('',(1.,0.,0.));
#1316=VECTOR('',#1315,1.);
#1317=CARTESIAN_POINT('',(-1.143,3.05411496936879,-9.21477922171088));
#1318=LINE('',#1317,#1316);
#1319=EDGE_CURVE('E535',#542,#978,#1318,.T.);
#1320=ORIENTED_EDGE('',*,*,#1319,.T.);
#1321=EDGE_LOOP('',(#1312,#1313,#1314,#1320));
#1322=FACE_BOUND('',#1321,.T.);
#1323=ADVANCED_FACE('F964',(#1322),#1311,.F.);
#1324=CARTESIAN_POINT('',(-1.143,3.05411496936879,-9.21477922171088));
#1325=DIRECTION('',(0.,0.782158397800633,0.62307964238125));
#1326=DIRECTION('',(0.,-0.62307964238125,0.782158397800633));
#1327=AXIS2_PLACEMENT_3D('',#1324,#1325,#1326);
#1328=PLANE('',#1327);
#1329=ORIENTED_EDGE('',*,*,#985,.T.);
#1330=ORIENTED_EDGE('',*,*,#1319,.F.);
#1331=ORIENTED_EDGE('',*,*,#543,.F.);
#1332=ORIENTED_EDGE('',*,*,#312,.T.);
#1333=EDGE_LOOP('',(#1329,#1330,#1331,#1332));
#1334=FACE_BOUND('',#1333,.T.);
#1335=ADVANCED_FACE('F966',(#1334),#1328,.F.);
#1336=CARTESIAN_POINT('',(-1.143,-3.0541149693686,-9.21477922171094));
#1337=DIRECTION('',(0.,-0.782158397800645,0.623079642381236));
#1338=DIRECTION('',(0.,-0.623079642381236,-0.782158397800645));
#1339=AXIS2_PLACEMENT_3D('',#1336,#1337,#1338);
#1340=PLANE('',#1339);
#1341=ORIENTED_EDGE('',*,*,#948,.T.);
#1342=ORIENTED_EDGE('',*,*,#270,.F.);
#1343=ORIENTED_EDGE('',*,*,#580,.F.);
#1344=DIRECTION('',(1.,0.,0.));
#1345=VECTOR('',#1344,1.);
#1346=CARTESIAN_POINT('',(-1.143,-3.0541149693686,-9.21477922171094));
#1347=LINE('',#1346,#1345);
#1348=EDGE_CURVE('E564',#573,#947,#1347,.T.);
#1349=ORIENTED_EDGE('',*,*,#1348,.T.);
#1350=EDGE_LOOP('',(#1341,#1342,#1343,#1349));
#1351=FACE_BOUND('',#1350,.T.);
#1352=ADVANCED_FACE('F951',(#1351),#1340,.F.);
#1353=CARTESIAN_POINT('',(-1.143,-1.24648035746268,-9.62736002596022));
#1354=DIRECTION('',(0.,0.222520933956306,0.974927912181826));
#1355=DIRECTION('',(0.,-0.974927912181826,0.222520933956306));
#1356=AXIS2_PLACEMENT_3D('',#1353,#1354,#1355);
#1357=PLANE('',#1356);
#1358=ORIENTED_EDGE('',*,*,#956,.T.);
#1359=ORIENTED_EDGE('',*,*,#1348,.F.);
#1360=ORIENTED_EDGE('',*,*,#574,.F.);
#1361=DIRECTION('',(1.,0.,0.));
#1362=VECTOR('',#1361,1.);
#1363=CARTESIAN_POINT('',(-1.143,-1.24648035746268,-9.62736002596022));
#1364=LINE('',#1363,#1362);
#1365=EDGE_CURVE('E561',#565,#955,#1364,.T.);
#1366=ORIENTED_EDGE('',*,*,#1365,.T.);
#1367=EDGE_LOOP('',(#1358,#1359,#1360,#1366));
#1368=FACE_BOUND('',#1367,.T.);
#1369=ADVANCED_FACE('F954',(#1368),#1357,.F.);
#1370=CARTESIAN_POINT('',(-1.143,-1.24648035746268,-9.62736002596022));
#1371=DIRECTION('',(0.,0.975044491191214,0.222009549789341));
#1372=DIRECTION('',(0.,-0.222009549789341,0.975044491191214));
#1373=AXIS2_PLACEMENT_3D('',#1370,#1371,#1372);
#1374=PLANE('',#1373);
#1375=ORIENTED_EDGE('',*,*,#962,.T.);
#1376=ORIENTED_EDGE('',*,*,#1365,.F.);
#1377=ORIENTED_EDGE('',*,*,#566,.F.);
#1378=ORIENTED_EDGE('',*,*,#285,.T.);
#1379=EDGE_LOOP('',(#1375,#1376,#1377,#1378));
#1380=FACE_BOUND('',#1379,.T.);
#1381=ADVANCED_FACE('F956',(#1380),#1374,.F.);
#1382=CARTESIAN_POINT('',(-1.143,-6.74980537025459,-6.97709838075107));
#1383=DIRECTION('',(0.,-0.434356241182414,0.900741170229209));
#1384=DIRECTION('',(0.,-0.900741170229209,-0.434356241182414));
#1385=AXIS2_PLACEMENT_3D('',#1382,#1383,#1384);
#1386=PLANE('',#1385);
#1387=ORIENTED_EDGE('',*,*,#925,.T.);
#1388=ORIENTED_EDGE('',*,*,#243,.F.);
#1389=ORIENTED_EDGE('',*,*,#603,.F.);
#1390=DIRECTION('',(1.,0.,0.));
#1391=VECTOR('',#1390,1.);
#1392=CARTESIAN_POINT('',(-1.143,-6.74980537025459,-6.97709838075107));
#1393=LINE('',#1392,#1391);
#1394=EDGE_CURVE('E590',#596,#924,#1393,.T.);
#1395=ORIENTED_EDGE('',*,*,#1394,.T.);
#1396=EDGE_LOOP('',(#1387,#1388,#1389,#1395));
#1397=FACE_BOUND('',#1396,.T.);
#1398=ADVANCED_FACE('F941',(#1397),#1386,.F.);
#1399=CARTESIAN_POINT('',(-1.143,-5.30019496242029,-8.13312410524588));
#1400=DIRECTION('',(0.,0.623489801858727,0.781831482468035));
#1401=DIRECTION('',(0.,-0.781831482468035,0.623489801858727));
#1402=AXIS2_PLACEMENT_3D('',#1399,#1400,#1401);
#1403=PLANE('',#1402);
#1404=ORIENTED_EDGE('',*,*,#933,.T.);
#1405=ORIENTED_EDGE('',*,*,#1394,.F.);
#1406=ORIENTED_EDGE('',*,*,#597,.F.);
#1407=DIRECTION('',(1.,0.,0.));
#1408=VECTOR('',#1407,1.);
#1409=CARTESIAN_POINT('',(-1.143,-5.30019496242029,-8.13312410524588));
#1410=LINE('',#1409,#1408);
#1411=EDGE_CURVE('E587',#588,#932,#1410,.T.);
#1412=ORIENTED_EDGE('',*,*,#1411,.T.);
#1413=EDGE_LOOP('',(#1404,#1405,#1406,#1412));
#1414=FACE_BOUND('',#1413,.T.);
#1415=ADVANCED_FACE('F944',(#1414),#1403,.F.);
#1416=CARTESIAN_POINT('',(-1.143,-5.30019496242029,-8.13312410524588));
#1417=DIRECTION('',(0.,0.974811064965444,-0.223032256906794));
#1418=DIRECTION('',(0.,0.223032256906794,0.974811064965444));
#1419=AXIS2_PLACEMENT_3D('',#1416,#1417,#1418);
#1420=PLANE('',#1419);
#1421=ORIENTED_EDGE('',*,*,#939,.T.);
#1422=ORIENTED_EDGE('',*,*,#1411,.F.);
#1423=ORIENTED_EDGE('',*,*,#589,.F.);
#1424=ORIENTED_EDGE('',*,*,#258,.T.);
#1425=EDGE_LOOP('',(#1421,#1422,#1423,#1424));
#1426=FACE_BOUND('',#1425,.T.);
#1427=ADVANCED_FACE('F946',(#1426),#1420,.F.);
#1428=CARTESIAN_POINT('',(-1.143,-9.10861403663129,-3.35751763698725));
#1429=DIRECTION('',(0.,-0.000524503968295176,0.999999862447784));
#1430=DIRECTION('',(0.,-0.999999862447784,-0.000524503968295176));
#1431=AXIS2_PLACEMENT_3D('',#1428,#1429,#1430);
#1432=PLANE('',#1431);
#1433=ORIENTED_EDGE('',*,*,#902,.T.);
#1434=ORIENTED_EDGE('',*,*,#216,.F.);
#1435=ORIENTED_EDGE('',*,*,#626,.F.);
#1436=DIRECTION('',(1.,0.,0.));
#1437=VECTOR('',#1436,1.);
#1438=CARTESIAN_POINT('',(-1.143,-9.10861403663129,-3.35751763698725));
#1439=LINE('',#1438,#1437);
#1440=EDGE_CURVE('E616',#619,#901,#1439,.T.);
#1441=ORIENTED_EDGE('',*,*,#1440,.T.);
#1442=EDGE_LOOP('',(#1433,#1434,#1435,#1441));
#1443=FACE_BOUND('',#1442,.T.);
#1444=ADVANCED_FACE('F931',(#1443),#1432,.F.);
#1445=CARTESIAN_POINT('',(-1.143,-8.30414095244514,-5.02802320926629));
#1446=DIRECTION('',(0.,0.900968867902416,0.433883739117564));
#1447=DIRECTION('',(0.,-0.433883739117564,0.900968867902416));
#1448=AXIS2_PLACEMENT_3D('',#1445,#1446,#1447);
#1449=PLANE('',#1448);
#1450=ORIENTED_EDGE('',*,*,#910,.T.);
#1451=ORIENTED_EDGE('',*,*,#1440,.F.);
#1452=ORIENTED_EDGE('',*,*,#620,.F.);
#1453=DIRECTION('',(1.,0.,0.));
#1454=VECTOR('',#1453,1.);
#1455=CARTESIAN_POINT('',(-1.143,-8.30414095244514,-5.02802320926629));
#1456=LINE('',#1455,#1454);
#1457=EDGE_CURVE('E613',#611,#909,#1456,.T.);
#1458=ORIENTED_EDGE('',*,*,#1457,.T.);
#1459=EDGE_LOOP('',(#1450,#1451,#1452,#1458));
#1460=FACE_BOUND('',#1459,.T.);
#1461=ADVANCED_FACE('F934',(#1460),#1449,.F.);
#1462=CARTESIAN_POINT('',(-1.143,-8.30414095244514,-5.02802320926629));
#1463=DIRECTION('',(0.,0.781504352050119,-0.623899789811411));
#1464=DIRECTION('',(0.,0.623899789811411,0.781504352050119));
#1465=AXIS2_PLACEMENT_3D('',#1462,#1463,#1464);
#1466=PLANE('',#1465);
#1467=ORIENTED_EDGE('',*,*,#916,.T.);
#1468=ORIENTED_EDGE('',*,*,#1457,.F.);
#1469=ORIENTED_EDGE('',*,*,#612,.F.);
#1470=ORIENTED_EDGE('',*,*,#231,.T.);
#1471=EDGE_LOOP('',(#1467,#1468,#1469,#1470));
#1472=FACE_BOUND('',#1471,.T.);
#1473=ADVANCED_FACE('F936',(#1472),#1466,.F.);
#1474=CARTESIAN_POINT('',(-1.143,-9.66334998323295,0.927060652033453));
#1475=DIRECTION('',(0.,0.433411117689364,0.9011963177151));
#1476=DIRECTION('',(0.,-0.901196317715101,0.433411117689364));
#1477=AXIS2_PLACEMENT_3D('',#1474,#1475,#1476);
#1478=PLANE('',#1477);
#1479=ORIENTED_EDGE('',*,*,#879,.T.);
#1480=ORIENTED_EDGE('',*,*,#189,.F.);
#1481=ORIENTED_EDGE('',*,*,#649,.F.);
#1482=DIRECTION('',(1.,0.,0.));
#1483=VECTOR('',#1482,1.);
#1484=CARTESIAN_POINT('',(-1.143,-9.66334998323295,0.927060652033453));
#1485=LINE('',#1484,#1483);
#1486=EDGE_CURVE('E642',#642,#878,#1485,.T.);
#1487=ORIENTED_EDGE('',*,*,#1486,.T.);
#1488=EDGE_LOOP('',(#1479,#1480,#1481,#1487));
#1489=FACE_BOUND('',#1488,.T.);
#1490=ADVANCED_FACE('F921',(#1489),#1478,.F.);
#1491=CARTESIAN_POINT('',(-1.143,-9.66334998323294,-0.92706065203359));
#1492=DIRECTION('',(0.,1.,0.));
#1493=DIRECTION('',(0.,0.,1.));
#1494=AXIS2_PLACEMENT_3D('',#1491,#1492,#1493);
#1495=PLANE('',#1494);
#1496=ORIENTED_EDGE('',*,*,#887,.T.);
#1497=ORIENTED_EDGE('',*,*,#1486,.F.);
#1498=ORIENTED_EDGE('',*,*,#643,.F.);
#1499=DIRECTION('',(1.,0.,0.));
#1500=VECTOR('',#1499,1.);
#1501=CARTESIAN_POINT('',(-1.143,-9.66334998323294,-0.92706065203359));
#1502=LINE('',#1501,#1500);
#1503=EDGE_CURVE('E639',#634,#886,#1502,.T.);
#1504=ORIENTED_EDGE('',*,*,#1503,.T.);
#1505=EDGE_LOOP('',(#1496,#1497,#1498,#1504));
#1506=FACE_BOUND('',#1505,.T.);
#1507=ADVANCED_FACE('F924',(#1506),#1495,.F.);
#1508=CARTESIAN_POINT('',(-1.143,-9.66334998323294,-0.92706065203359));
#1509=DIRECTION('',(0.,0.433411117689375,-0.901196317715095));
#1510=DIRECTION('',(0.,0.901196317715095,0.433411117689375));
#1511=AXIS2_PLACEMENT_3D('',#1508,#1509,#1510);
#1512=PLANE('',#1511);
#1513=ORIENTED_EDGE('',*,*,#893,.T.);
#1514=ORIENTED_EDGE('',*,*,#1503,.F.);
#1515=ORIENTED_EDGE('',*,*,#635,.F.);
#1516=ORIENTED_EDGE('',*,*,#204,.T.);
#1517=EDGE_LOOP('',(#1513,#1514,#1515,#1516));
#1518=FACE_BOUND('',#1517,.T.);
#1519=ADVANCED_FACE('F926',(#1518),#1512,.F.);
#1520=CARTESIAN_POINT('',(-1.143,-8.30414095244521,5.02802320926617));
#1521=DIRECTION('',(0.,0.781504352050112,0.623899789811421));
#1522=DIRECTION('',(0.,-0.623899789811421,0.781504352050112));
#1523=AXIS2_PLACEMENT_3D('',#1520,#1521,#1522);
#1524=PLANE('',#1523);
#1525=ORIENTED_EDGE('',*,*,#856,.T.);
#1526=ORIENTED_EDGE('',*,*,#162,.F.);
#1527=ORIENTED_EDGE('',*,*,#672,.F.);
#1528=DIRECTION('',(1.,0.,0.));
#1529=VECTOR('',#1528,1.);
#1530=CARTESIAN_POINT('',(-1.143,-8.30414095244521,5.02802320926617));
#1531=LINE('',#1530,#1529);
#1532=EDGE_CURVE('E668',#665,#855,#1531,.T.);
#1533=ORIENTED_EDGE('',*,*,#1532,.T.);
#1534=EDGE_LOOP('',(#1525,#1526,#1527,#1533));
#1535=FACE_BOUND('',#1534,.T.);
#1536=ADVANCED_FACE('F911',(#1535),#1524,.F.);
#1537=CARTESIAN_POINT('',(-1.143,-9.10861403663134,3.35751763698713));
#1538=DIRECTION('',(0.,0.900968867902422,-0.433883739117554));
#1539=DIRECTION('',(0.,0.433883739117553,0.900968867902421));
#1540=AXIS2_PLACEMENT_3D('',#1537,#1538,#1539);
#1541=PLANE('',#1540);
#1542=ORIENTED_EDGE('',*,*,#864,.T.);
#1543=ORIENTED_EDGE('',*,*,#1532,.F.);
#1544=ORIENTED_EDGE('',*,*,#666,.F.);
#1545=DIRECTION('',(1.,0.,0.));
#1546=VECTOR('',#1545,1.);
#1547=CARTESIAN_POINT('',(-1.143,-9.10861403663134,3.35751763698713));
#1548=LINE('',#1547,#1546);
#1549=EDGE_CURVE('E665',#657,#863,#1548,.T.);
#1550=ORIENTED_EDGE('',*,*,#1549,.T.);
#1551=EDGE_LOOP('',(#1542,#1543,#1544,#1550));
#1552=FACE_BOUND('',#1551,.T.);
#1553=ADVANCED_FACE('F914',(#1552),#1541,.F.);
#1554=CARTESIAN_POINT('',(-1.143,-9.10861403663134,3.35751763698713));
#1555=DIRECTION('',(0.,-0.000524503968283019,-0.999999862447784));
#1556=DIRECTION('',(0.,0.999999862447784,-0.000524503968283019));
#1557=AXIS2_PLACEMENT_3D('',#1554,#1555,#1556);
#1558=PLANE('',#1557);
#1559=ORIENTED_EDGE('',*,*,#870,.T.);
#1560=ORIENTED_EDGE('',*,*,#1549,.F.);
#1561=ORIENTED_EDGE('',*,*,#658,.F.);
#1562=ORIENTED_EDGE('',*,*,#177,.T.);
#1563=EDGE_LOOP('',(#1559,#1560,#1561,#1562));
#1564=FACE_BOUND('',#1563,.T.);
#1565=ADVANCED_FACE('F916',(#1564),#1558,.F.);
#1566=CARTESIAN_POINT('',(-1.143,-5.3001949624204,8.13312410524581));
#1567=DIRECTION('',(0.,0.974811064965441,0.223032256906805));
#1568=DIRECTION('',(0.,-0.223032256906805,0.974811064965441));
#1569=AXIS2_PLACEMENT_3D('',#1566,#1567,#1568);
#1570=PLANE('',#1569);
#1571=ORIENTED_EDGE('',*,*,#833,.T.);
#1572=ORIENTED_EDGE('',*,*,#135,.F.);
#1573=ORIENTED_EDGE('',*,*,#695,.F.);
#1574=DIRECTION('',(1.,0.,0.));
#1575=VECTOR('',#1574,1.);
#1576=CARTESIAN_POINT('',(-1.143,-5.3001949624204,8.13312410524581));
#1577=LINE('',#1576,#1575);
#1578=EDGE_CURVE('E694',#688,#832,#1577,.T.);
#1579=ORIENTED_EDGE('',*,*,#1578,.T.);
#1580=EDGE_LOOP('',(#1571,#1572,#1573,#1579));
#1581=FACE_BOUND('',#1580,.T.);
#1582=ADVANCED_FACE('F901',(#1581),#1570,.F.);
#1583=CARTESIAN_POINT('',(-1.143,-6.74980537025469,6.97709838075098));
#1584=DIRECTION('',(0.,0.623489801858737,-0.781831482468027));
#1585=DIRECTION('',(0.,0.781831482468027,0.623489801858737));
#1586=AXIS2_PLACEMENT_3D('',#1583,#1584,#1585);
#1587=PLANE('',#1586);
#1588=ORIENTED_EDGE('',*,*,#841,.T.);
#1589=ORIENTED_EDGE('',*,*,#1578,.F.);
#1590=ORIENTED_EDGE('',*,*,#689,.F.);
#1591=DIRECTION('',(1.,0.,0.));
#1592=VECTOR('',#1591,1.);
#1593=CARTESIAN_POINT('',(-1.143,-6.74980537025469,6.97709838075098));
#1594=LINE('',#1593,#1592);
#1595=EDGE_CURVE('E691',#680,#840,#1594,.T.);
#1596=ORIENTED_EDGE('',*,*,#1595,.T.);
#1597=EDGE_LOOP('',(#1588,#1589,#1590,#1596));
#1598=FACE_BOUND('',#1597,.T.);
#1599=ADVANCED_FACE('F904',(#1598),#1587,.F.);
#1600=CARTESIAN_POINT('',(-1.143,-6.74980537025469,6.97709838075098));
#1601=DIRECTION('',(0.,-0.434356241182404,-0.900741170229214));
#1602=DIRECTION('',(0.,0.900741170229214,-0.434356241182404));
#1603=AXIS2_PLACEMENT_3D('',#1600,#1601,#1602);
#1604=PLANE('',#1603);
#1605=ORIENTED_EDGE('',*,*,#847,.T.);
#1606=ORIENTED_EDGE('',*,*,#1595,.F.);
#1607=ORIENTED_EDGE('',*,*,#681,.F.);
#1608=ORIENTED_EDGE('',*,*,#150,.T.);
#1609=EDGE_LOOP('',(#1605,#1606,#1607,#1608));
#1610=FACE_BOUND('',#1609,.T.);
#1611=ADVANCED_FACE('F906',(#1610),#1604,.F.);
#1612=CARTESIAN_POINT('',(-1.143,-1.24648035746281,9.6273600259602));
#1613=DIRECTION('',(0.,0.975044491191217,-0.22200954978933));
#1614=DIRECTION('',(0.,0.22200954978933,0.975044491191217));
#1615=AXIS2_PLACEMENT_3D('',#1612,#1613,#1614);
#1616=PLANE('',#1615);
#1617=ORIENTED_EDGE('',*,*,#810,.T.);
#1618=ORIENTED_EDGE('',*,*,#108,.F.);
#1619=ORIENTED_EDGE('',*,*,#718,.F.);
#1620=DIRECTION('',(1.,0.,0.));
#1621=VECTOR('',#1620,1.);
#1622=CARTESIAN_POINT('',(-1.143,-1.24648035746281,9.6273600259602));
#1623=LINE('',#1622,#1621);
#1624=EDGE_CURVE('E720',#711,#809,#1623,.T.);
#1625=ORIENTED_EDGE('',*,*,#1624,.T.);
#1626=EDGE_LOOP('',(#1617,#1618,#1619,#1625));
#1627=FACE_BOUND('',#1626,.T.);
#1628=ADVANCED_FACE('F1285',(#1627),#1616,.F.);
#1629=CARTESIAN_POINT('',(-1.143,-3.05411496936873,9.2147792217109));
#1630=DIRECTION('',(0.,0.222520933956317,-0.974927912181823));
#1631=DIRECTION('',(0.,0.974927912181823,0.222520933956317));
#1632=AXIS2_PLACEMENT_3D('',#1629,#1630,#1631);
#1633=PLANE('',#1632);
#1634=ORIENTED_EDGE('',*,*,#818,.T.);
#1635=ORIENTED_EDGE('',*,*,#1624,.F.);
#1636=ORIENTED_EDGE('',*,*,#712,.F.);
#1637=DIRECTION('',(1.,0.,0.));
#1638=VECTOR('',#1637,1.);
#1639=CARTESIAN_POINT('',(-1.143,-3.05411496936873,9.2147792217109));
#1640=LINE('',#1639,#1638);
#1641=EDGE_CURVE('E717',#703,#817,#1640,.T.);
#1642=ORIENTED_EDGE('',*,*,#1641,.T.);
#1643=EDGE_LOOP('',(#1634,#1635,#1636,#1642));
#1644=FACE_BOUND('',#1643,.T.);
#1645=ADVANCED_FACE('F1294',(#1644),#1633,.F.);
#1646=CARTESIAN_POINT('',(-1.143,-3.05411496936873,9.2147792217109));
#1647=DIRECTION('',(0.,-0.782158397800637,-0.623079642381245));
#1648=DIRECTION('',(0.,0.623079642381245,-0.782158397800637));
#1649=AXIS2_PLACEMENT_3D('',#1646,#1647,#1648);
#1650=PLANE('',#1649);
#1651=ORIENTED_EDGE('',*,*,#824,.T.);
#1652=ORIENTED_EDGE('',*,*,#1641,.F.);
#1653=ORIENTED_EDGE('',*,*,#704,.F.);
#1654=ORIENTED_EDGE('',*,*,#123,.T.);
#1655=EDGE_LOOP('',(#1651,#1652,#1653,#1654));
#1656=FACE_BOUND('',#1655,.T.);
#1657=ADVANCED_FACE('F1304',(#1656),#1650,.F.);
#1658=CARTESIAN_POINT('',(-1.143,3.05411496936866,9.21477922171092));
#1659=DIRECTION('',(0.,0.78215839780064,-0.623079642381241));
#1660=DIRECTION('',(0.,0.623079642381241,0.782158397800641));
#1661=AXIS2_PLACEMENT_3D('',#1658,#1659,#1660);
#1662=PLANE('',#1661);
#1663=ORIENTED_EDGE('',*,*,#787,.T.);
#1664=ORIENTED_EDGE('',*,*,#81,.F.);
#1665=ORIENTED_EDGE('',*,*,#741,.F.);
#1666=DIRECTION('',(1.,0.,0.));
#1667=VECTOR('',#1666,1.);
#1668=CARTESIAN_POINT('',(-1.143,3.05411496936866,9.21477922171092));
#1669=LINE('',#1668,#1667);
#1670=EDGE_CURVE('E745',#734,#786,#1669,.T.);
#1671=ORIENTED_EDGE('',*,*,#1670,.T.);
#1672=EDGE_LOOP('',(#1663,#1664,#1665,#1671));
#1673=FACE_BOUND('',#1672,.T.);
#1674=ADVANCED_FACE('F1314',(#1673),#1662,.F.);
#1675=CARTESIAN_POINT('',(-1.143,1.24648035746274,9.62736002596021));
#1676=DIRECTION('',(0.,-0.222520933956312,-0.974927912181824));
#1677=DIRECTION('',(0.,0.974927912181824,-0.222520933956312));
#1678=AXIS2_PLACEMENT_3D('',#1675,#1676,#1677);
#1679=PLANE('',#1678);
#1680=ORIENTED_EDGE('',*,*,#795,.T.);
#1681=ORIENTED_EDGE('',*,*,#1670,.F.);
#1682=ORIENTED_EDGE('',*,*,#735,.F.);
#1683=DIRECTION('',(1.,0.,0.));
#1684=VECTOR('',#1683,1.);
#1685=CARTESIAN_POINT('',(-1.143,1.24648035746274,9.62736002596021));
#1686=LINE('',#1685,#1684);
#1687=EDGE_CURVE('E743',#726,#794,#1686,.T.);
#1688=ORIENTED_EDGE('',*,*,#1687,.T.);
#1689=EDGE_LOOP('',(#1680,#1681,#1682,#1688));
#1690=FACE_BOUND('',#1689,.T.);
#1691=ADVANCED_FACE('F1324',(#1690),#1679,.F.);
#1692=CARTESIAN_POINT('',(-1.143,1.24648035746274,9.62736002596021));
#1693=DIRECTION('',(0.,-0.975044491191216,-0.222009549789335));
#1694=DIRECTION('',(0.,0.222009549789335,-0.975044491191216));
#1695=AXIS2_PLACEMENT_3D('',#1692,#1693,#1694);
#1696=PLANE('',#1695);
#1697=ORIENTED_EDGE('',*,*,#801,.T.);
#1698=ORIENTED_EDGE('',*,*,#1687,.F.);
#1699=ORIENTED_EDGE('',*,*,#727,.F.);
#1700=ORIENTED_EDGE('',*,*,#96,.T.);
#1701=EDGE_LOOP('',(#1697,#1698,#1699,#1700));
#1702=FACE_BOUND('',#1701,.T.);
#1703=ADVANCED_FACE('F1334',(#1702),#1696,.F.);
#1704=CARTESIAN_POINT('',(-1.143,6.74980537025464,6.97709838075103));
#1705=DIRECTION('',(0.,0.434356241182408,-0.900741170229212));
#1706=DIRECTION('',(0.,0.900741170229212,0.434356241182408));
#1707=AXIS2_PLACEMENT_3D('',#1704,#1705,#1706);
#1708=PLANE('',#1707);
#1709=ORIENTED_EDGE('',*,*,#764,.T.);
#1710=ORIENTED_EDGE('',*,*,#32,.F.);
#1711=ORIENTED_EDGE('',*,*,#442,.F.);
#1712=DIRECTION('',(1.,0.,0.));
#1713=VECTOR('',#1712,1.);
#1714=CARTESIAN_POINT('',(-1.143,6.74980537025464,6.97709838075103));
#1715=LINE('',#1714,#1713);
#1716=EDGE_CURVE('E764',#435,#763,#1715,.T.);
#1717=ORIENTED_EDGE('',*,*,#1716,.T.);
#1718=EDGE_LOOP('',(#1709,#1710,#1711,#1717));
#1719=FACE_BOUND('',#1718,.T.);
#1720=ADVANCED_FACE('F782',(#1719),#1708,.F.);
#1721=CARTESIAN_POINT('',(-1.143,5.30019496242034,8.13312410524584));
#1722=DIRECTION('',(0.,-0.623489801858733,-0.78183148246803));
#1723=DIRECTION('',(0.,0.781831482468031,-0.623489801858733));
#1724=AXIS2_PLACEMENT_3D('',#1721,#1722,#1723);
#1725=PLANE('',#1724);
#1726=ORIENTED_EDGE('',*,*,#772,.T.);
#1727=ORIENTED_EDGE('',*,*,#1716,.F.);
#1728=ORIENTED_EDGE('',*,*,#436,.F.);
#1729=DIRECTION('',(1.,0.,0.));
#1730=VECTOR('',#1729,1.);
#1731=CARTESIAN_POINT('',(-1.143,5.30019496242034,8.13312410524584));
#1732=LINE('',#1731,#1730);
#1733=EDGE_CURVE('E395',#433,#771,#1732,.T.);
#1734=ORIENTED_EDGE('',*,*,#1733,.T.);
#1735=EDGE_LOOP('',(#1726,#1727,#1728,#1734));
#1736=FACE_BOUND('',#1735,.T.);
#1737=ADVANCED_FACE('F778',(#1736),#1725,.F.);
#1738=CARTESIAN_POINT('',(-1.143,5.30019496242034,8.13312410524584));
#1739=DIRECTION('',(0.,-0.974811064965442,0.2230322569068));
#1740=DIRECTION('',(0.,-0.2230322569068,-0.974811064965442));
#1741=AXIS2_PLACEMENT_3D('',#1738,#1739,#1740);
#1742=PLANE('',#1741);
#1743=ORIENTED_EDGE('',*,*,#778,.T.);
#1744=ORIENTED_EDGE('',*,*,#1733,.F.);
#1745=ORIENTED_EDGE('',*,*,#748,.F.);
#1746=ORIENTED_EDGE('',*,*,#69,.T.);
#1747=EDGE_LOOP('',(#1743,#1744,#1745,#1746));
#1748=FACE_BOUND('',#1747,.T.);
#1749=ADVANCED_FACE('F392',(#1748),#1742,.F.);
#1750=CLOSED_SHELL('',(#60,#87,#114,#141,#168,#195,#222,#249,#276,#303,#330,#357,#384,#411,#752,
#1093,#1105,#1122,#1139,#1151,#1168,#1185,#1197,#1214,#1231,#1243,#1260,#1277,#1289,#1306,#1323,
#1335,#1352,#1369,#1381,#1398,#1415,#1427,#1444,#1461,#1473,#1490,#1507,#1519,#1536,#1553,#1565,
#1582,#1599,#1611,#1628,#1645,#1657,#1674,#1691,#1703,#1720,#1737,#1749));
#1751=MANIFOLD_SOLID_BREP('B2',#1750);
#1752=ADVANCED_BREP_SHAPE_REPRESENTATION('',(#18,#1751),#14);
#1753=SHAPE_DEFINITION_REPRESENTATION(#9,#1752);
ENDSEC;
END-ISO-10303-21;
